###############################################################
#  Generated by:      Cadence Innovus 23.14-s088_1
#  OS:                Linux x86_64(Host ID user1-EliteMini)
#  Generated on:      Tue Oct 13 20:43:39 2026
#  Design:            top_soc
#  Command:           write_lef_abstract -noCutObs ./outputs/top_soc.lef
###############################################################

VERSION 5.8 ;

BUSBITCHARS "[]" ;
DIVIDERCHAR "/" ;

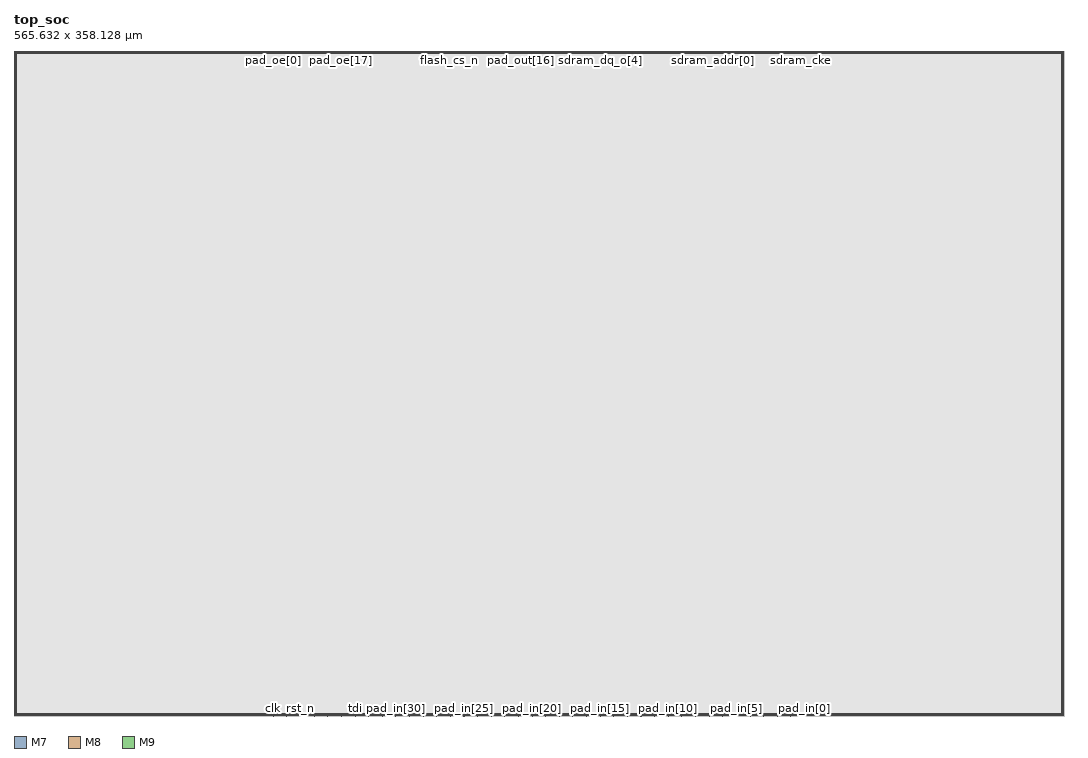
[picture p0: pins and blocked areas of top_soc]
MACRO top_soc
  CLASS BLOCK ;
  SIZE 565.632000 BY 358.128000 ;
  FOREIGN top_soc 0.000000 0.000000 ;
  ORIGIN 0 0 ;
  SYMMETRY X Y R90 ;
  PIN clk
    DIRECTION INPUT ;
    USE SIGNAL ;
    PORT
      LAYER M7 ;
        RECT 139.668000 0.000000 139.700000 0.072000 ;
    END
  END clk
  PIN rtc_clk
    DIRECTION INPUT ;
    USE SIGNAL ;
    PORT
      LAYER M7 ;
        RECT 146.964000 0.000000 146.996000 0.072000 ;
    END
  END rtc_clk
  PIN rst_n
    DIRECTION INPUT ;
    USE SIGNAL ;
    PORT
      LAYER M7 ;
        RECT 154.324000 0.000000 154.356000 0.072000 ;
    END
  END rst_n
  PIN tck
    DIRECTION INPUT ;
    USE SIGNAL ;
    PORT
      LAYER M7 ;
        RECT 161.684000 0.000000 161.716000 0.072000 ;
    END
  END tck
  PIN trst_n
    DIRECTION INPUT ;
    USE SIGNAL ;
    PORT
      LAYER M7 ;
        RECT 168.980000 0.000000 169.012000 0.072000 ;
    END
  END trst_n
  PIN tms
    DIRECTION INPUT ;
    USE SIGNAL ;
    PORT
      LAYER M7 ;
        RECT 176.340000 0.000000 176.372000 0.072000 ;
    END
  END tms
  PIN tdi
    DIRECTION INPUT ;
    USE SIGNAL ;
    PORT
      LAYER M7 ;
        RECT 183.700000 0.000000 183.732000 0.072000 ;
    END
  END tdi
  PIN tdo
    DIRECTION OUTPUT ;
    USE SIGNAL ;
    PORT
      LAYER M7 ;
        RECT 190.996000 0.000000 191.028000 0.072000 ;
    END
  END tdo
  PIN pad_in[31]
    DIRECTION INPUT ;
    USE SIGNAL ;
    PORT
      LAYER M7 ;
        RECT 198.356000 0.000000 198.388000 0.072000 ;
    END
  END pad_in[31]
  PIN pad_in[30]
    DIRECTION INPUT ;
    USE SIGNAL ;
    PORT
      LAYER M7 ;
        RECT 205.716000 0.000000 205.748000 0.072000 ;
    END
  END pad_in[30]
  PIN pad_in[29]
    DIRECTION INPUT ;
    USE SIGNAL ;
    PORT
      LAYER M7 ;
        RECT 213.012000 0.000000 213.044000 0.072000 ;
    END
  END pad_in[29]
  PIN pad_in[28]
    DIRECTION INPUT ;
    USE SIGNAL ;
    PORT
      LAYER M7 ;
        RECT 220.372000 0.000000 220.404000 0.072000 ;
    END
  END pad_in[28]
  PIN pad_in[27]
    DIRECTION INPUT ;
    USE SIGNAL ;
    PORT
      LAYER M7 ;
        RECT 227.732000 0.000000 227.764000 0.072000 ;
    END
  END pad_in[27]
  PIN pad_in[26]
    DIRECTION INPUT ;
    USE SIGNAL ;
    PORT
      LAYER M7 ;
        RECT 235.028000 0.000000 235.060000 0.072000 ;
    END
  END pad_in[26]
  PIN pad_in[25]
    DIRECTION INPUT ;
    USE SIGNAL ;
    PORT
      LAYER M7 ;
        RECT 242.388000 0.000000 242.420000 0.072000 ;
    END
  END pad_in[25]
  PIN pad_in[24]
    DIRECTION INPUT ;
    USE SIGNAL ;
    PORT
      LAYER M7 ;
        RECT 249.748000 0.000000 249.780000 0.072000 ;
    END
  END pad_in[24]
  PIN pad_in[23]
    DIRECTION INPUT ;
    USE SIGNAL ;
    PORT
      LAYER M7 ;
        RECT 257.044000 0.000000 257.076000 0.072000 ;
    END
  END pad_in[23]
  PIN pad_in[22]
    DIRECTION INPUT ;
    USE SIGNAL ;
    PORT
      LAYER M7 ;
        RECT 264.404000 0.000000 264.436000 0.072000 ;
    END
  END pad_in[22]
  PIN pad_in[21]
    DIRECTION INPUT ;
    USE SIGNAL ;
    PORT
      LAYER M7 ;
        RECT 271.764000 0.000000 271.796000 0.072000 ;
    END
  END pad_in[21]
  PIN pad_in[20]
    DIRECTION INPUT ;
    USE SIGNAL ;
    PORT
      LAYER M7 ;
        RECT 279.060000 0.000000 279.092000 0.072000 ;
    END
  END pad_in[20]
  PIN pad_in[19]
    DIRECTION INPUT ;
    USE SIGNAL ;
    PORT
      LAYER M7 ;
        RECT 286.420000 0.000000 286.452000 0.072000 ;
    END
  END pad_in[19]
  PIN pad_in[18]
    DIRECTION INPUT ;
    USE SIGNAL ;
    PORT
      LAYER M7 ;
        RECT 293.780000 0.000000 293.812000 0.072000 ;
    END
  END pad_in[18]
  PIN pad_in[17]
    DIRECTION INPUT ;
    USE SIGNAL ;
    PORT
      LAYER M7 ;
        RECT 301.076000 0.000000 301.108000 0.072000 ;
    END
  END pad_in[17]
  PIN pad_in[16]
    DIRECTION INPUT ;
    USE SIGNAL ;
    PORT
      LAYER M7 ;
        RECT 308.436000 0.000000 308.468000 0.072000 ;
    END
  END pad_in[16]
  PIN pad_in[15]
    DIRECTION INPUT ;
    USE SIGNAL ;
    PORT
      LAYER M7 ;
        RECT 315.732000 0.000000 315.764000 0.072000 ;
    END
  END pad_in[15]
  PIN pad_in[14]
    DIRECTION INPUT ;
    USE SIGNAL ;
    PORT
      LAYER M7 ;
        RECT 323.092000 0.000000 323.124000 0.072000 ;
    END
  END pad_in[14]
  PIN pad_in[13]
    DIRECTION INPUT ;
    USE SIGNAL ;
    PORT
      LAYER M7 ;
        RECT 330.452000 0.000000 330.484000 0.072000 ;
    END
  END pad_in[13]
  PIN pad_in[12]
    DIRECTION INPUT ;
    USE SIGNAL ;
    PORT
      LAYER M7 ;
        RECT 337.748000 0.000000 337.780000 0.072000 ;
    END
  END pad_in[12]
  PIN pad_in[11]
    DIRECTION INPUT ;
    USE SIGNAL ;
    PORT
      LAYER M7 ;
        RECT 345.108000 0.000000 345.140000 0.072000 ;
    END
  END pad_in[11]
  PIN pad_in[10]
    DIRECTION INPUT ;
    USE SIGNAL ;
    PORT
      LAYER M7 ;
        RECT 352.468000 0.000000 352.500000 0.072000 ;
    END
  END pad_in[10]
  PIN pad_in[9]
    DIRECTION INPUT ;
    USE SIGNAL ;
    PORT
      LAYER M7 ;
        RECT 359.764000 0.000000 359.796000 0.072000 ;
    END
  END pad_in[9]
  PIN pad_in[8]
    DIRECTION INPUT ;
    USE SIGNAL ;
    PORT
      LAYER M7 ;
        RECT 367.124000 0.000000 367.156000 0.072000 ;
    END
  END pad_in[8]
  PIN pad_in[7]
    DIRECTION INPUT ;
    USE SIGNAL ;
    PORT
      LAYER M7 ;
        RECT 374.484000 0.000000 374.516000 0.072000 ;
    END
  END pad_in[7]
  PIN pad_in[6]
    DIRECTION INPUT ;
    USE SIGNAL ;
    PORT
      LAYER M7 ;
        RECT 381.780000 0.000000 381.812000 0.072000 ;
    END
  END pad_in[6]
  PIN pad_in[5]
    DIRECTION INPUT ;
    USE SIGNAL ;
    PORT
      LAYER M7 ;
        RECT 389.140000 0.000000 389.172000 0.072000 ;
    END
  END pad_in[5]
  PIN pad_in[4]
    DIRECTION INPUT ;
    USE SIGNAL ;
    PORT
      LAYER M7 ;
        RECT 396.500000 0.000000 396.532000 0.072000 ;
    END
  END pad_in[4]
  PIN pad_in[3]
    DIRECTION INPUT ;
    USE SIGNAL ;
    PORT
      LAYER M7 ;
        RECT 403.796000 0.000000 403.828000 0.072000 ;
    END
  END pad_in[3]
  PIN pad_in[2]
    DIRECTION INPUT ;
    USE SIGNAL ;
    PORT
      LAYER M7 ;
        RECT 411.156000 0.000000 411.188000 0.072000 ;
    END
  END pad_in[2]
  PIN pad_in[1]
    DIRECTION INPUT ;
    USE SIGNAL ;
    PORT
      LAYER M7 ;
        RECT 418.516000 0.000000 418.548000 0.072000 ;
    END
  END pad_in[1]
  PIN pad_in[0]
    DIRECTION INPUT ;
    USE SIGNAL ;
    PORT
      LAYER M7 ;
        RECT 425.812000 0.000000 425.844000 0.072000 ;
    END
  END pad_in[0]
  PIN pad_out[31]
    DIRECTION OUTPUT ;
    USE SIGNAL ;
    PORT
      LAYER M7 ;
        RECT 305.428000 358.056000 305.460000 358.128000 ;
    END
  END pad_out[31]
  PIN pad_out[30]
    DIRECTION OUTPUT ;
    USE SIGNAL ;
    PORT
      LAYER M7 ;
        RECT 303.252000 358.056000 303.284000 358.128000 ;
    END
  END pad_out[30]
  PIN pad_out[29]
    DIRECTION OUTPUT ;
    USE SIGNAL ;
    PORT
      LAYER M7 ;
        RECT 301.076000 358.056000 301.108000 358.128000 ;
    END
  END pad_out[29]
  PIN pad_out[28]
    DIRECTION OUTPUT ;
    USE SIGNAL ;
    PORT
      LAYER M7 ;
        RECT 298.964000 358.056000 298.996000 358.128000 ;
    END
  END pad_out[28]
  PIN pad_out[27]
    DIRECTION OUTPUT ;
    USE SIGNAL ;
    PORT
      LAYER M7 ;
        RECT 296.788000 358.056000 296.820000 358.128000 ;
    END
  END pad_out[27]
  PIN pad_out[26]
    DIRECTION OUTPUT ;
    USE SIGNAL ;
    PORT
      LAYER M7 ;
        RECT 294.612000 358.056000 294.644000 358.128000 ;
    END
  END pad_out[26]
  PIN pad_out[25]
    DIRECTION OUTPUT ;
    USE SIGNAL ;
    PORT
      LAYER M7 ;
        RECT 292.500000 358.056000 292.532000 358.128000 ;
    END
  END pad_out[25]
  PIN pad_out[24]
    DIRECTION OUTPUT ;
    USE SIGNAL ;
    PORT
      LAYER M7 ;
        RECT 290.324000 358.056000 290.356000 358.128000 ;
    END
  END pad_out[24]
  PIN pad_out[23]
    DIRECTION OUTPUT ;
    USE SIGNAL ;
    PORT
      LAYER M7 ;
        RECT 288.212000 358.056000 288.244000 358.128000 ;
    END
  END pad_out[23]
  PIN pad_out[22]
    DIRECTION OUTPUT ;
    USE SIGNAL ;
    PORT
      LAYER M7 ;
        RECT 286.036000 358.056000 286.068000 358.128000 ;
    END
  END pad_out[22]
  PIN pad_out[21]
    DIRECTION OUTPUT ;
    USE SIGNAL ;
    PORT
      LAYER M7 ;
        RECT 283.860000 358.056000 283.892000 358.128000 ;
    END
  END pad_out[21]
  PIN pad_out[20]
    DIRECTION OUTPUT ;
    USE SIGNAL ;
    PORT
      LAYER M7 ;
        RECT 281.748000 358.056000 281.780000 358.128000 ;
    END
  END pad_out[20]
  PIN pad_out[19]
    DIRECTION OUTPUT ;
    USE SIGNAL ;
    PORT
      LAYER M7 ;
        RECT 279.572000 358.056000 279.604000 358.128000 ;
    END
  END pad_out[19]
  PIN pad_out[18]
    DIRECTION OUTPUT ;
    USE SIGNAL ;
    PORT
      LAYER M7 ;
        RECT 277.396000 358.056000 277.428000 358.128000 ;
    END
  END pad_out[18]
  PIN pad_out[17]
    DIRECTION OUTPUT ;
    USE SIGNAL ;
    PORT
      LAYER M7 ;
        RECT 275.284000 358.056000 275.316000 358.128000 ;
    END
  END pad_out[17]
  PIN pad_out[16]
    DIRECTION OUTPUT ;
    USE SIGNAL ;
    PORT
      LAYER M7 ;
        RECT 273.108000 358.056000 273.140000 358.128000 ;
    END
  END pad_out[16]
  PIN pad_out[15]
    DIRECTION OUTPUT ;
    USE SIGNAL ;
    PORT
      LAYER M7 ;
        RECT 270.996000 358.056000 271.028000 358.128000 ;
    END
  END pad_out[15]
  PIN pad_out[14]
    DIRECTION OUTPUT ;
    USE SIGNAL ;
    PORT
      LAYER M7 ;
        RECT 268.820000 358.056000 268.852000 358.128000 ;
    END
  END pad_out[14]
  PIN pad_out[13]
    DIRECTION OUTPUT ;
    USE SIGNAL ;
    PORT
      LAYER M7 ;
        RECT 266.644000 358.056000 266.676000 358.128000 ;
    END
  END pad_out[13]
  PIN pad_out[12]
    DIRECTION OUTPUT ;
    USE SIGNAL ;
    PORT
      LAYER M7 ;
        RECT 264.532000 358.056000 264.564000 358.128000 ;
    END
  END pad_out[12]
  PIN pad_out[11]
    DIRECTION OUTPUT ;
    USE SIGNAL ;
    PORT
      LAYER M7 ;
        RECT 262.356000 358.056000 262.388000 358.128000 ;
    END
  END pad_out[11]
  PIN pad_out[10]
    DIRECTION OUTPUT ;
    USE SIGNAL ;
    PORT
      LAYER M7 ;
        RECT 260.180000 358.056000 260.212000 358.128000 ;
    END
  END pad_out[10]
  PIN pad_out[9]
    DIRECTION OUTPUT ;
    USE SIGNAL ;
    PORT
      LAYER M7 ;
        RECT 258.068000 358.056000 258.100000 358.128000 ;
    END
  END pad_out[9]
  PIN pad_out[8]
    DIRECTION OUTPUT ;
    USE SIGNAL ;
    PORT
      LAYER M7 ;
        RECT 255.892000 358.056000 255.924000 358.128000 ;
    END
  END pad_out[8]
  PIN pad_out[7]
    DIRECTION OUTPUT ;
    USE SIGNAL ;
    PORT
      LAYER M7 ;
        RECT 253.780000 358.056000 253.812000 358.128000 ;
    END
  END pad_out[7]
  PIN pad_out[6]
    DIRECTION OUTPUT ;
    USE SIGNAL ;
    PORT
      LAYER M7 ;
        RECT 251.604000 358.056000 251.636000 358.128000 ;
    END
  END pad_out[6]
  PIN pad_out[5]
    DIRECTION OUTPUT ;
    USE SIGNAL ;
    PORT
      LAYER M7 ;
        RECT 249.428000 358.056000 249.460000 358.128000 ;
    END
  END pad_out[5]
  PIN pad_out[4]
    DIRECTION OUTPUT ;
    USE SIGNAL ;
    PORT
      LAYER M7 ;
        RECT 247.316000 358.056000 247.348000 358.128000 ;
    END
  END pad_out[4]
  PIN pad_out[3]
    DIRECTION OUTPUT ;
    USE SIGNAL ;
    PORT
      LAYER M7 ;
        RECT 245.140000 358.056000 245.172000 358.128000 ;
    END
  END pad_out[3]
  PIN pad_out[2]
    DIRECTION OUTPUT ;
    USE SIGNAL ;
    PORT
      LAYER M7 ;
        RECT 242.964000 358.056000 242.996000 358.128000 ;
    END
  END pad_out[2]
  PIN pad_out[1]
    DIRECTION OUTPUT ;
    USE SIGNAL ;
    PORT
      LAYER M7 ;
        RECT 240.852000 358.056000 240.884000 358.128000 ;
    END
  END pad_out[1]
  PIN pad_out[0]
    DIRECTION OUTPUT ;
    USE SIGNAL ;
    PORT
      LAYER M7 ;
        RECT 238.676000 358.056000 238.708000 358.128000 ;
    END
  END pad_out[0]
  PIN pad_oe[31]
    DIRECTION OUTPUT ;
    USE SIGNAL ;
    PORT
      LAYER M7 ;
        RECT 206.420000 358.056000 206.452000 358.128000 ;
    END
  END pad_oe[31]
  PIN pad_oe[30]
    DIRECTION OUTPUT ;
    USE SIGNAL ;
    PORT
      LAYER M7 ;
        RECT 204.244000 358.056000 204.276000 358.128000 ;
    END
  END pad_oe[30]
  PIN pad_oe[29]
    DIRECTION OUTPUT ;
    USE SIGNAL ;
    PORT
      LAYER M7 ;
        RECT 202.132000 358.056000 202.164000 358.128000 ;
    END
  END pad_oe[29]
  PIN pad_oe[28]
    DIRECTION OUTPUT ;
    USE SIGNAL ;
    PORT
      LAYER M7 ;
        RECT 199.956000 358.056000 199.988000 358.128000 ;
    END
  END pad_oe[28]
  PIN pad_oe[27]
    DIRECTION OUTPUT ;
    USE SIGNAL ;
    PORT
      LAYER M7 ;
        RECT 197.780000 358.056000 197.812000 358.128000 ;
    END
  END pad_oe[27]
  PIN pad_oe[26]
    DIRECTION OUTPUT ;
    USE SIGNAL ;
    PORT
      LAYER M7 ;
        RECT 195.668000 358.056000 195.700000 358.128000 ;
    END
  END pad_oe[26]
  PIN pad_oe[25]
    DIRECTION OUTPUT ;
    USE SIGNAL ;
    PORT
      LAYER M7 ;
        RECT 193.492000 358.056000 193.524000 358.128000 ;
    END
  END pad_oe[25]
  PIN pad_oe[24]
    DIRECTION OUTPUT ;
    USE SIGNAL ;
    PORT
      LAYER M7 ;
        RECT 191.316000 358.056000 191.348000 358.128000 ;
    END
  END pad_oe[24]
  PIN pad_oe[23]
    DIRECTION OUTPUT ;
    USE SIGNAL ;
    PORT
      LAYER M7 ;
        RECT 189.204000 358.056000 189.236000 358.128000 ;
    END
  END pad_oe[23]
  PIN pad_oe[22]
    DIRECTION OUTPUT ;
    USE SIGNAL ;
    PORT
      LAYER M7 ;
        RECT 187.028000 358.056000 187.060000 358.128000 ;
    END
  END pad_oe[22]
  PIN pad_oe[21]
    DIRECTION OUTPUT ;
    USE SIGNAL ;
    PORT
      LAYER M7 ;
        RECT 184.916000 358.056000 184.948000 358.128000 ;
    END
  END pad_oe[21]
  PIN pad_oe[20]
    DIRECTION OUTPUT ;
    USE SIGNAL ;
    PORT
      LAYER M7 ;
        RECT 182.740000 358.056000 182.772000 358.128000 ;
    END
  END pad_oe[20]
  PIN pad_oe[19]
    DIRECTION OUTPUT ;
    USE SIGNAL ;
    PORT
      LAYER M7 ;
        RECT 180.564000 358.056000 180.596000 358.128000 ;
    END
  END pad_oe[19]
  PIN pad_oe[18]
    DIRECTION OUTPUT ;
    USE SIGNAL ;
    PORT
      LAYER M7 ;
        RECT 178.452000 358.056000 178.484000 358.128000 ;
    END
  END pad_oe[18]
  PIN pad_oe[17]
    DIRECTION OUTPUT ;
    USE SIGNAL ;
    PORT
      LAYER M7 ;
        RECT 176.276000 358.056000 176.308000 358.128000 ;
    END
  END pad_oe[17]
  PIN pad_oe[16]
    DIRECTION OUTPUT ;
    USE SIGNAL ;
    PORT
      LAYER M7 ;
        RECT 174.100000 358.056000 174.132000 358.128000 ;
    END
  END pad_oe[16]
  PIN pad_oe[15]
    DIRECTION OUTPUT ;
    USE SIGNAL ;
    PORT
      LAYER M7 ;
        RECT 171.988000 358.056000 172.020000 358.128000 ;
    END
  END pad_oe[15]
  PIN pad_oe[14]
    DIRECTION OUTPUT ;
    USE SIGNAL ;
    PORT
      LAYER M7 ;
        RECT 169.812000 358.056000 169.844000 358.128000 ;
    END
  END pad_oe[14]
  PIN pad_oe[13]
    DIRECTION OUTPUT ;
    USE SIGNAL ;
    PORT
      LAYER M7 ;
        RECT 167.700000 358.056000 167.732000 358.128000 ;
    END
  END pad_oe[13]
  PIN pad_oe[12]
    DIRECTION OUTPUT ;
    USE SIGNAL ;
    PORT
      LAYER M7 ;
        RECT 165.524000 358.056000 165.556000 358.128000 ;
    END
  END pad_oe[12]
  PIN pad_oe[11]
    DIRECTION OUTPUT ;
    USE SIGNAL ;
    PORT
      LAYER M7 ;
        RECT 163.348000 358.056000 163.380000 358.128000 ;
    END
  END pad_oe[11]
  PIN pad_oe[10]
    DIRECTION OUTPUT ;
    USE SIGNAL ;
    PORT
      LAYER M7 ;
        RECT 161.236000 358.056000 161.268000 358.128000 ;
    END
  END pad_oe[10]
  PIN pad_oe[9]
    DIRECTION OUTPUT ;
    USE SIGNAL ;
    PORT
      LAYER M7 ;
        RECT 159.060000 358.056000 159.092000 358.128000 ;
    END
  END pad_oe[9]
  PIN pad_oe[8]
    DIRECTION OUTPUT ;
    USE SIGNAL ;
    PORT
      LAYER M7 ;
        RECT 156.884000 358.056000 156.916000 358.128000 ;
    END
  END pad_oe[8]
  PIN pad_oe[7]
    DIRECTION OUTPUT ;
    USE SIGNAL ;
    PORT
      LAYER M7 ;
        RECT 154.772000 358.056000 154.804000 358.128000 ;
    END
  END pad_oe[7]
  PIN pad_oe[6]
    DIRECTION OUTPUT ;
    USE SIGNAL ;
    PORT
      LAYER M7 ;
        RECT 152.596000 358.056000 152.628000 358.128000 ;
    END
  END pad_oe[6]
  PIN pad_oe[5]
    DIRECTION OUTPUT ;
    USE SIGNAL ;
    PORT
      LAYER M7 ;
        RECT 150.484000 358.056000 150.516000 358.128000 ;
    END
  END pad_oe[5]
  PIN pad_oe[4]
    DIRECTION OUTPUT ;
    USE SIGNAL ;
    PORT
      LAYER M7 ;
        RECT 148.308000 358.056000 148.340000 358.128000 ;
    END
  END pad_oe[4]
  PIN pad_oe[3]
    DIRECTION OUTPUT ;
    USE SIGNAL ;
    PORT
      LAYER M7 ;
        RECT 146.132000 358.056000 146.164000 358.128000 ;
    END
  END pad_oe[3]
  PIN pad_oe[2]
    DIRECTION OUTPUT ;
    USE SIGNAL ;
    PORT
      LAYER M7 ;
        RECT 144.020000 358.056000 144.052000 358.128000 ;
    END
  END pad_oe[2]
  PIN pad_oe[1]
    DIRECTION OUTPUT ;
    USE SIGNAL ;
    PORT
      LAYER M7 ;
        RECT 141.844000 358.056000 141.876000 358.128000 ;
    END
  END pad_oe[1]
  PIN pad_oe[0]
    DIRECTION OUTPUT ;
    USE SIGNAL ;
    PORT
      LAYER M7 ;
        RECT 139.668000 358.056000 139.700000 358.128000 ;
    END
  END pad_oe[0]
  PIN flash_sck
    DIRECTION OUTPUT ;
    USE SIGNAL ;
    PORT
      LAYER M7 ;
        RECT 236.564000 358.056000 236.596000 358.128000 ;
    END
  END flash_sck
  PIN flash_cs_n
    DIRECTION OUTPUT ;
    USE SIGNAL ;
    PORT
      LAYER M7 ;
        RECT 234.388000 358.056000 234.420000 358.128000 ;
    END
  END flash_cs_n
  PIN flash_io_i[3]
    DIRECTION INPUT ;
    USE SIGNAL ;
    PORT
      LAYER M7 ;
        RECT 232.212000 358.056000 232.244000 358.128000 ;
    END
  END flash_io_i[3]
  PIN flash_io_i[2]
    DIRECTION INPUT ;
    USE SIGNAL ;
    PORT
      LAYER M7 ;
        RECT 230.100000 358.056000 230.132000 358.128000 ;
    END
  END flash_io_i[2]
  PIN flash_io_i[1]
    DIRECTION INPUT ;
    USE SIGNAL ;
    PORT
      LAYER M7 ;
        RECT 227.924000 358.056000 227.956000 358.128000 ;
    END
  END flash_io_i[1]
  PIN flash_io_i[0]
    DIRECTION INPUT ;
    USE SIGNAL ;
    PORT
      LAYER M7 ;
        RECT 225.748000 358.056000 225.780000 358.128000 ;
    END
  END flash_io_i[0]
  PIN flash_io_o[3]
    DIRECTION OUTPUT ;
    USE SIGNAL ;
    PORT
      LAYER M7 ;
        RECT 223.636000 358.056000 223.668000 358.128000 ;
    END
  END flash_io_o[3]
  PIN flash_io_o[2]
    DIRECTION OUTPUT ;
    USE SIGNAL ;
    PORT
      LAYER M7 ;
        RECT 221.460000 358.056000 221.492000 358.128000 ;
    END
  END flash_io_o[2]
  PIN flash_io_o[1]
    DIRECTION OUTPUT ;
    USE SIGNAL ;
    PORT
      LAYER M7 ;
        RECT 219.348000 358.056000 219.380000 358.128000 ;
    END
  END flash_io_o[1]
  PIN flash_io_o[0]
    DIRECTION OUTPUT ;
    USE SIGNAL ;
    PORT
      LAYER M7 ;
        RECT 217.172000 358.056000 217.204000 358.128000 ;
    END
  END flash_io_o[0]
  PIN flash_io_oe[3]
    DIRECTION OUTPUT ;
    USE SIGNAL ;
    PORT
      LAYER M7 ;
        RECT 214.996000 358.056000 215.028000 358.128000 ;
    END
  END flash_io_oe[3]
  PIN flash_io_oe[2]
    DIRECTION OUTPUT ;
    USE SIGNAL ;
    PORT
      LAYER M7 ;
        RECT 212.884000 358.056000 212.916000 358.128000 ;
    END
  END flash_io_oe[2]
  PIN flash_io_oe[1]
    DIRECTION OUTPUT ;
    USE SIGNAL ;
    PORT
      LAYER M7 ;
        RECT 210.708000 358.056000 210.740000 358.128000 ;
    END
  END flash_io_oe[1]
  PIN flash_io_oe[0]
    DIRECTION OUTPUT ;
    USE SIGNAL ;
    PORT
      LAYER M7 ;
        RECT 208.532000 358.056000 208.564000 358.128000 ;
    END
  END flash_io_oe[0]
  PIN sdram_clk
    DIRECTION OUTPUT ;
    USE SIGNAL ;
    PORT
      LAYER M7 ;
        RECT 425.876000 358.056000 425.908000 358.128000 ;
    END
  END sdram_clk
  PIN sdram_cke
    DIRECTION OUTPUT ;
    USE SIGNAL ;
    PORT
      LAYER M7 ;
        RECT 423.764000 358.056000 423.796000 358.128000 ;
    END
  END sdram_cke
  PIN sdram_cs_n
    DIRECTION OUTPUT ;
    USE SIGNAL ;
    PORT
      LAYER M7 ;
        RECT 421.588000 358.056000 421.620000 358.128000 ;
    END
  END sdram_cs_n
  PIN sdram_ras_n
    DIRECTION OUTPUT ;
    USE SIGNAL ;
    PORT
      LAYER M7 ;
        RECT 419.476000 358.056000 419.508000 358.128000 ;
    END
  END sdram_ras_n
  PIN sdram_cas_n
    DIRECTION OUTPUT ;
    USE SIGNAL ;
    PORT
      LAYER M7 ;
        RECT 417.300000 358.056000 417.332000 358.128000 ;
    END
  END sdram_cas_n
  PIN sdram_we_n
    DIRECTION OUTPUT ;
    USE SIGNAL ;
    PORT
      LAYER M7 ;
        RECT 415.124000 358.056000 415.156000 358.128000 ;
    END
  END sdram_we_n
  PIN sdram_ba[1]
    DIRECTION OUTPUT ;
    USE SIGNAL ;
    PORT
      LAYER M7 ;
        RECT 410.836000 358.056000 410.868000 358.128000 ;
    END
  END sdram_ba[1]
  PIN sdram_ba[0]
    DIRECTION OUTPUT ;
    USE SIGNAL ;
    PORT
      LAYER M7 ;
        RECT 408.724000 358.056000 408.756000 358.128000 ;
    END
  END sdram_ba[0]
  PIN sdram_addr[12]
    DIRECTION OUTPUT ;
    USE SIGNAL ;
    PORT
      LAYER M7 ;
        RECT 402.260000 358.056000 402.292000 358.128000 ;
    END
  END sdram_addr[12]
  PIN sdram_addr[11]
    DIRECTION OUTPUT ;
    USE SIGNAL ;
    PORT
      LAYER M7 ;
        RECT 400.084000 358.056000 400.116000 358.128000 ;
    END
  END sdram_addr[11]
  PIN sdram_addr[10]
    DIRECTION OUTPUT ;
    USE SIGNAL ;
    PORT
      LAYER M7 ;
        RECT 397.908000 358.056000 397.940000 358.128000 ;
    END
  END sdram_addr[10]
  PIN sdram_addr[9]
    DIRECTION OUTPUT ;
    USE SIGNAL ;
    PORT
      LAYER M7 ;
        RECT 395.796000 358.056000 395.828000 358.128000 ;
    END
  END sdram_addr[9]
  PIN sdram_addr[8]
    DIRECTION OUTPUT ;
    USE SIGNAL ;
    PORT
      LAYER M7 ;
        RECT 393.620000 358.056000 393.652000 358.128000 ;
    END
  END sdram_addr[8]
  PIN sdram_addr[7]
    DIRECTION OUTPUT ;
    USE SIGNAL ;
    PORT
      LAYER M7 ;
        RECT 391.508000 358.056000 391.540000 358.128000 ;
    END
  END sdram_addr[7]
  PIN sdram_addr[6]
    DIRECTION OUTPUT ;
    USE SIGNAL ;
    PORT
      LAYER M7 ;
        RECT 389.332000 358.056000 389.364000 358.128000 ;
    END
  END sdram_addr[6]
  PIN sdram_addr[5]
    DIRECTION OUTPUT ;
    USE SIGNAL ;
    PORT
      LAYER M7 ;
        RECT 387.156000 358.056000 387.188000 358.128000 ;
    END
  END sdram_addr[5]
  PIN sdram_addr[4]
    DIRECTION OUTPUT ;
    USE SIGNAL ;
    PORT
      LAYER M7 ;
        RECT 385.044000 358.056000 385.076000 358.128000 ;
    END
  END sdram_addr[4]
  PIN sdram_addr[3]
    DIRECTION OUTPUT ;
    USE SIGNAL ;
    PORT
      LAYER M7 ;
        RECT 382.868000 358.056000 382.900000 358.128000 ;
    END
  END sdram_addr[3]
  PIN sdram_addr[2]
    DIRECTION OUTPUT ;
    USE SIGNAL ;
    PORT
      LAYER M7 ;
        RECT 380.692000 358.056000 380.724000 358.128000 ;
    END
  END sdram_addr[2]
  PIN sdram_addr[1]
    DIRECTION OUTPUT ;
    USE SIGNAL ;
    PORT
      LAYER M7 ;
        RECT 378.580000 358.056000 378.612000 358.128000 ;
    END
  END sdram_addr[1]
  PIN sdram_addr[0]
    DIRECTION OUTPUT ;
    USE SIGNAL ;
    PORT
      LAYER M7 ;
        RECT 376.404000 358.056000 376.436000 358.128000 ;
    END
  END sdram_addr[0]
  PIN sdram_dq_i[15]
    DIRECTION INPUT ;
    USE SIGNAL ;
    PORT
      LAYER M7 ;
        RECT 374.292000 358.056000 374.324000 358.128000 ;
    END
  END sdram_dq_i[15]
  PIN sdram_dq_i[14]
    DIRECTION INPUT ;
    USE SIGNAL ;
    PORT
      LAYER M7 ;
        RECT 372.116000 358.056000 372.148000 358.128000 ;
    END
  END sdram_dq_i[14]
  PIN sdram_dq_i[13]
    DIRECTION INPUT ;
    USE SIGNAL ;
    PORT
      LAYER M7 ;
        RECT 369.940000 358.056000 369.972000 358.128000 ;
    END
  END sdram_dq_i[13]
  PIN sdram_dq_i[12]
    DIRECTION INPUT ;
    USE SIGNAL ;
    PORT
      LAYER M7 ;
        RECT 367.828000 358.056000 367.860000 358.128000 ;
    END
  END sdram_dq_i[12]
  PIN sdram_dq_i[11]
    DIRECTION INPUT ;
    USE SIGNAL ;
    PORT
      LAYER M7 ;
        RECT 365.652000 358.056000 365.684000 358.128000 ;
    END
  END sdram_dq_i[11]
  PIN sdram_dq_i[10]
    DIRECTION INPUT ;
    USE SIGNAL ;
    PORT
      LAYER M7 ;
        RECT 363.476000 358.056000 363.508000 358.128000 ;
    END
  END sdram_dq_i[10]
  PIN sdram_dq_i[9]
    DIRECTION INPUT ;
    USE SIGNAL ;
    PORT
      LAYER M7 ;
        RECT 361.364000 358.056000 361.396000 358.128000 ;
    END
  END sdram_dq_i[9]
  PIN sdram_dq_i[8]
    DIRECTION INPUT ;
    USE SIGNAL ;
    PORT
      LAYER M7 ;
        RECT 359.188000 358.056000 359.220000 358.128000 ;
    END
  END sdram_dq_i[8]
  PIN sdram_dq_i[7]
    DIRECTION INPUT ;
    USE SIGNAL ;
    PORT
      LAYER M7 ;
        RECT 357.076000 358.056000 357.108000 358.128000 ;
    END
  END sdram_dq_i[7]
  PIN sdram_dq_i[6]
    DIRECTION INPUT ;
    USE SIGNAL ;
    PORT
      LAYER M7 ;
        RECT 354.900000 358.056000 354.932000 358.128000 ;
    END
  END sdram_dq_i[6]
  PIN sdram_dq_i[5]
    DIRECTION INPUT ;
    USE SIGNAL ;
    PORT
      LAYER M7 ;
        RECT 352.724000 358.056000 352.756000 358.128000 ;
    END
  END sdram_dq_i[5]
  PIN sdram_dq_i[4]
    DIRECTION INPUT ;
    USE SIGNAL ;
    PORT
      LAYER M7 ;
        RECT 350.612000 358.056000 350.644000 358.128000 ;
    END
  END sdram_dq_i[4]
  PIN sdram_dq_i[3]
    DIRECTION INPUT ;
    USE SIGNAL ;
    PORT
      LAYER M7 ;
        RECT 348.436000 358.056000 348.468000 358.128000 ;
    END
  END sdram_dq_i[3]
  PIN sdram_dq_i[2]
    DIRECTION INPUT ;
    USE SIGNAL ;
    PORT
      LAYER M7 ;
        RECT 346.260000 358.056000 346.292000 358.128000 ;
    END
  END sdram_dq_i[2]
  PIN sdram_dq_i[1]
    DIRECTION INPUT ;
    USE SIGNAL ;
    PORT
      LAYER M7 ;
        RECT 344.148000 358.056000 344.180000 358.128000 ;
    END
  END sdram_dq_i[1]
  PIN sdram_dq_i[0]
    DIRECTION INPUT ;
    USE SIGNAL ;
    PORT
      LAYER M7 ;
        RECT 341.972000 358.056000 342.004000 358.128000 ;
    END
  END sdram_dq_i[0]
  PIN sdram_dq_o[15]
    DIRECTION OUTPUT ;
    USE SIGNAL ;
    PORT
      LAYER M7 ;
        RECT 339.860000 358.056000 339.892000 358.128000 ;
    END
  END sdram_dq_o[15]
  PIN sdram_dq_o[14]
    DIRECTION OUTPUT ;
    USE SIGNAL ;
    PORT
      LAYER M7 ;
        RECT 337.684000 358.056000 337.716000 358.128000 ;
    END
  END sdram_dq_o[14]
  PIN sdram_dq_o[13]
    DIRECTION OUTPUT ;
    USE SIGNAL ;
    PORT
      LAYER M7 ;
        RECT 335.508000 358.056000 335.540000 358.128000 ;
    END
  END sdram_dq_o[13]
  PIN sdram_dq_o[12]
    DIRECTION OUTPUT ;
    USE SIGNAL ;
    PORT
      LAYER M7 ;
        RECT 333.396000 358.056000 333.428000 358.128000 ;
    END
  END sdram_dq_o[12]
  PIN sdram_dq_o[11]
    DIRECTION OUTPUT ;
    USE SIGNAL ;
    PORT
      LAYER M7 ;
        RECT 331.220000 358.056000 331.252000 358.128000 ;
    END
  END sdram_dq_o[11]
  PIN sdram_dq_o[10]
    DIRECTION OUTPUT ;
    USE SIGNAL ;
    PORT
      LAYER M7 ;
        RECT 329.044000 358.056000 329.076000 358.128000 ;
    END
  END sdram_dq_o[10]
  PIN sdram_dq_o[9]
    DIRECTION OUTPUT ;
    USE SIGNAL ;
    PORT
      LAYER M7 ;
        RECT 326.932000 358.056000 326.964000 358.128000 ;
    END
  END sdram_dq_o[9]
  PIN sdram_dq_o[8]
    DIRECTION OUTPUT ;
    USE SIGNAL ;
    PORT
      LAYER M7 ;
        RECT 324.756000 358.056000 324.788000 358.128000 ;
    END
  END sdram_dq_o[8]
  PIN sdram_dq_o[7]
    DIRECTION OUTPUT ;
    USE SIGNAL ;
    PORT
      LAYER M7 ;
        RECT 322.644000 358.056000 322.676000 358.128000 ;
    END
  END sdram_dq_o[7]
  PIN sdram_dq_o[6]
    DIRECTION OUTPUT ;
    USE SIGNAL ;
    PORT
      LAYER M7 ;
        RECT 320.468000 358.056000 320.500000 358.128000 ;
    END
  END sdram_dq_o[6]
  PIN sdram_dq_o[5]
    DIRECTION OUTPUT ;
    USE SIGNAL ;
    PORT
      LAYER M7 ;
        RECT 318.292000 358.056000 318.324000 358.128000 ;
    END
  END sdram_dq_o[5]
  PIN sdram_dq_o[4]
    DIRECTION OUTPUT ;
    USE SIGNAL ;
    PORT
      LAYER M7 ;
        RECT 316.180000 358.056000 316.212000 358.128000 ;
    END
  END sdram_dq_o[4]
  PIN sdram_dq_o[3]
    DIRECTION OUTPUT ;
    USE SIGNAL ;
    PORT
      LAYER M7 ;
        RECT 314.004000 358.056000 314.036000 358.128000 ;
    END
  END sdram_dq_o[3]
  PIN sdram_dq_o[2]
    DIRECTION OUTPUT ;
    USE SIGNAL ;
    PORT
      LAYER M7 ;
        RECT 311.828000 358.056000 311.860000 358.128000 ;
    END
  END sdram_dq_o[2]
  PIN sdram_dq_o[1]
    DIRECTION OUTPUT ;
    USE SIGNAL ;
    PORT
      LAYER M7 ;
        RECT 309.716000 358.056000 309.748000 358.128000 ;
    END
  END sdram_dq_o[1]
  PIN sdram_dq_o[0]
    DIRECTION OUTPUT ;
    USE SIGNAL ;
    PORT
      LAYER M7 ;
        RECT 307.540000 358.056000 307.572000 358.128000 ;
    END
  END sdram_dq_o[0]
  PIN sdram_dq_oe
    DIRECTION OUTPUT ;
    USE SIGNAL ;
    PORT
      LAYER M7 ;
        RECT 413.012000 358.056000 413.044000 358.128000 ;
    END
  END sdram_dq_oe
  PIN sdram_dqm[1]
    DIRECTION OUTPUT ;
    USE SIGNAL ;
    PORT
      LAYER M7 ;
        RECT 406.548000 358.056000 406.580000 358.128000 ;
    END
  END sdram_dqm[1]
  PIN sdram_dqm[0]
    DIRECTION OUTPUT ;
    USE SIGNAL ;
    PORT
      LAYER M7 ;
        RECT 404.372000 358.056000 404.404000 358.128000 ;
    END
  END sdram_dqm[0]
  PIN VDD
    DIRECTION INOUT ;
    USE POWER ;
    PORT
      LAYER M8 ;
        RECT 0.862000 0.836000 564.730000 1.316000 ;
    END
    PORT
      LAYER M9 ;
        RECT 564.276000 0.842000 564.756000 357.310000 ;
    END
    PORT
      LAYER M9 ;
        RECT 0.836000 0.842000 1.316000 357.310000 ;
    END
    PORT
      LAYER M8 ;
        RECT 0.862000 356.836000 564.730000 357.316000 ;
    END
  END VDD
  PIN VSS
    DIRECTION INOUT ;
    USE GROUND ;
    PORT
      LAYER M8 ;
        RECT 0.222000 0.196000 565.370000 0.676000 ;
    END
    PORT
      LAYER M9 ;
        RECT 564.916000 0.202000 565.396000 357.950000 ;
    END
    PORT
      LAYER M9 ;
        RECT 0.196000 0.202000 0.676000 357.950000 ;
    END
    PORT
      LAYER M8 ;
        RECT 0.222000 357.476000 565.370000 357.956000 ;
    END
  END VSS
  OBS
    LAYER M1 ;
      RECT 0.000000 0.000000 565.632000 358.128000 ;
    LAYER M2 ;
      RECT 0.000000 0.000000 565.632000 358.128000 ;
    LAYER M3 ;
      RECT 0.000000 0.000000 565.632000 358.128000 ;
    LAYER M4 ;
      RECT 0.000000 0.000000 565.632000 358.128000 ;
    LAYER M5 ;
      RECT 0.000000 0.000000 565.632000 358.128000 ;
    LAYER M6 ;
      RECT 0.000000 0.000000 565.632000 358.128000 ;
    LAYER M7 ;
      RECT 0.000000 0.000000 565.632000 358.128000 ;
    LAYER M8 ;
      RECT 0.000000 0.000000 565.632000 358.128000 ;
    LAYER M9 ;
      RECT 0.000000 0.000000 565.632000 358.128000 ;
    LAYER Pad ;
      RECT 0.000000 0.000000 565.632000 358.128000 ;
  END
  DENSITY
      LAYER M1 ;
      RECT 500.000000 300.000000 565.632000 358.128000 37.92 ;
      RECT 400.000000 300.000000 500.000000 358.128000 43.57 ;
      RECT 300.000000 300.000000 400.000000 358.128000 37.53 ;
      RECT 200.000000 300.000000 300.000000 358.128000 47.39 ;
      RECT 100.000000 300.000000 200.000000 358.128000 41.43 ;
      RECT 0.000000 300.000000 100.000000 358.128000 40.06 ;
      RECT 500.000000 200.000000 565.632000 300.000000 40.39 ;
      RECT 400.000000 200.000000 500.000000 300.000000 42.52 ;
      RECT 300.000000 200.000000 400.000000 300.000000 41.53 ;
      RECT 200.000000 200.000000 300.000000 300.000000 33.34 ;
      RECT 100.000000 200.000000 200.000000 300.000000 44.94 ;
      RECT 0.000000 200.000000 100.000000 300.000000 41.48 ;
      RECT 500.000000 100.000000 565.632000 200.000000 39.35 ;
      RECT 400.000000 100.000000 500.000000 200.000000 42.67 ;
      RECT 300.000000 100.000000 400.000000 200.000000 36.91 ;
      RECT 200.000000 100.000000 300.000000 200.000000 34.23 ;
      RECT 100.000000 100.000000 200.000000 200.000000 40.01 ;
      RECT 0.000000 100.000000 100.000000 200.000000 40.89 ;
      RECT 500.000000 0.000000 565.632000 100.000000 40.41 ;
      RECT 400.000000 0.000000 500.000000 100.000000 41.35 ;
      RECT 300.000000 0.000000 400.000000 100.000000 40.92 ;
      RECT 200.000000 0.000000 300.000000 100.000000 43.03 ;
      RECT 100.000000 0.000000 200.000000 100.000000 41.12 ;
      RECT 0.000000 0.000000 100.000000 100.000000 42.02 ;
      LAYER M2 ;
      RECT 500.000000 300.000000 565.632000 358.128000 39.38 ;
      RECT 400.000000 300.000000 500.000000 358.128000 48.11 ;
      RECT 300.000000 300.000000 400.000000 358.128000 40.33 ;
      RECT 200.000000 300.000000 300.000000 358.128000 58.59 ;
      RECT 100.000000 300.000000 200.000000 358.128000 40.24 ;
      RECT 0.000000 300.000000 100.000000 358.128000 40.35 ;
      RECT 500.000000 200.000000 565.632000 300.000000 40.83 ;
      RECT 400.000000 200.000000 500.000000 300.000000 44.44 ;
      RECT 300.000000 200.000000 400.000000 300.000000 40.22 ;
      RECT 200.000000 200.000000 300.000000 300.000000 27.41 ;
      RECT 100.000000 200.000000 200.000000 300.000000 47.89 ;
      RECT 0.000000 200.000000 100.000000 300.000000 41.41 ;
      RECT 500.000000 100.000000 565.632000 200.000000 39.12 ;
      RECT 400.000000 100.000000 500.000000 200.000000 44.75 ;
      RECT 300.000000 100.000000 400.000000 200.000000 34.01 ;
      RECT 200.000000 100.000000 300.000000 200.000000 28.47 ;
      RECT 100.000000 100.000000 200.000000 200.000000 40.02 ;
      RECT 0.000000 100.000000 100.000000 200.000000 40.69 ;
      RECT 500.000000 0.000000 565.632000 100.000000 40.71 ;
      RECT 400.000000 0.000000 500.000000 100.000000 41.89 ;
      RECT 300.000000 0.000000 400.000000 100.000000 41.57 ;
      RECT 200.000000 0.000000 300.000000 100.000000 44.63 ;
      RECT 100.000000 0.000000 200.000000 100.000000 42.34 ;
      RECT 0.000000 0.000000 100.000000 100.000000 41.98 ;
      LAYER M3 ;
      RECT 500.000000 300.000000 565.632000 358.128000 52.56 ;
      RECT 400.000000 300.000000 500.000000 358.128000 48.79 ;
      RECT 300.000000 300.000000 400.000000 358.128000 40.53 ;
      RECT 200.000000 300.000000 300.000000 358.128000 57.76 ;
      RECT 100.000000 300.000000 200.000000 358.128000 39.04 ;
      RECT 0.000000 300.000000 100.000000 358.128000 53.52 ;
      RECT 500.000000 200.000000 565.632000 300.000000 57.89 ;
      RECT 400.000000 200.000000 500.000000 300.000000 54.08 ;
      RECT 300.000000 200.000000 400.000000 300.000000 41.90 ;
      RECT 200.000000 200.000000 300.000000 300.000000 30.80 ;
      RECT 100.000000 200.000000 200.000000 300.000000 47.67 ;
      RECT 0.000000 200.000000 100.000000 300.000000 58.85 ;
      RECT 500.000000 100.000000 565.632000 200.000000 56.66 ;
      RECT 400.000000 100.000000 500.000000 200.000000 51.84 ;
      RECT 300.000000 100.000000 400.000000 200.000000 36.08 ;
      RECT 200.000000 100.000000 300.000000 200.000000 31.96 ;
      RECT 100.000000 100.000000 200.000000 200.000000 41.42 ;
      RECT 0.000000 100.000000 100.000000 200.000000 57.84 ;
      RECT 500.000000 0.000000 565.632000 100.000000 54.27 ;
      RECT 400.000000 0.000000 500.000000 100.000000 54.54 ;
      RECT 300.000000 0.000000 400.000000 100.000000 52.22 ;
      RECT 200.000000 0.000000 300.000000 100.000000 52.65 ;
      RECT 100.000000 0.000000 200.000000 100.000000 52.83 ;
      RECT 0.000000 0.000000 100.000000 100.000000 55.09 ;
      LAYER M4 ;
      RECT 500.000000 300.000000 565.632000 358.128000 16.36 ;
      RECT 400.000000 300.000000 500.000000 358.128000 28.46 ;
      RECT 300.000000 300.000000 400.000000 358.128000 25.22 ;
      RECT 200.000000 300.000000 300.000000 358.128000 34.71 ;
      RECT 100.000000 300.000000 200.000000 358.128000 26.57 ;
      RECT 0.000000 300.000000 100.000000 358.128000 16.80 ;
      RECT 500.000000 200.000000 565.632000 300.000000 15.03 ;
      RECT 400.000000 200.000000 500.000000 300.000000 24.42 ;
      RECT 300.000000 200.000000 400.000000 300.000000 27.43 ;
      RECT 200.000000 200.000000 300.000000 300.000000 24.05 ;
      RECT 100.000000 200.000000 200.000000 300.000000 29.73 ;
      RECT 0.000000 200.000000 100.000000 300.000000 15.50 ;
      RECT 500.000000 100.000000 565.632000 200.000000 15.88 ;
      RECT 400.000000 100.000000 500.000000 200.000000 26.77 ;
      RECT 300.000000 100.000000 400.000000 200.000000 26.54 ;
      RECT 200.000000 100.000000 300.000000 200.000000 26.69 ;
      RECT 100.000000 100.000000 200.000000 200.000000 26.40 ;
      RECT 0.000000 100.000000 100.000000 200.000000 16.26 ;
      RECT 500.000000 0.000000 565.632000 100.000000 16.24 ;
      RECT 400.000000 0.000000 500.000000 100.000000 16.78 ;
      RECT 300.000000 0.000000 400.000000 100.000000 15.29 ;
      RECT 200.000000 0.000000 300.000000 100.000000 18.29 ;
      RECT 100.000000 0.000000 200.000000 100.000000 17.08 ;
      RECT 0.000000 0.000000 100.000000 100.000000 16.60 ;
      LAYER M5 ;
      RECT 560.000000 340.000000 565.632000 358.128000 26.46 ;
      RECT 540.000000 340.000000 560.000000 358.128000 8.81 ;
      RECT 520.000000 340.000000 540.000000 358.128000 17.28 ;
      RECT 500.000000 340.000000 520.000000 358.128000 8.15 ;
      RECT 480.000000 340.000000 500.000000 358.128000 11.87 ;
      RECT 460.000000 340.000000 480.000000 358.128000 15.93 ;
      RECT 440.000000 340.000000 460.000000 358.128000 8.39 ;
      RECT 420.000000 340.000000 440.000000 358.128000 23.03 ;
      RECT 400.000000 340.000000 420.000000 358.128000 29.14 ;
      RECT 380.000000 340.000000 400.000000 358.128000 27.49 ;
      RECT 360.000000 340.000000 380.000000 358.128000 25.01 ;
      RECT 340.000000 340.000000 360.000000 358.128000 26.53 ;
      RECT 320.000000 340.000000 340.000000 358.128000 27.58 ;
      RECT 300.000000 340.000000 320.000000 358.128000 26.26 ;
      RECT 280.000000 340.000000 300.000000 358.128000 32.15 ;
      RECT 260.000000 340.000000 280.000000 358.128000 27.50 ;
      RECT 240.000000 340.000000 260.000000 358.128000 27.54 ;
      RECT 220.000000 340.000000 240.000000 358.128000 25.11 ;
      RECT 200.000000 340.000000 220.000000 358.128000 30.09 ;
      RECT 180.000000 340.000000 200.000000 358.128000 27.95 ;
      RECT 160.000000 340.000000 180.000000 358.128000 26.32 ;
      RECT 140.000000 340.000000 160.000000 358.128000 25.45 ;
      RECT 120.000000 340.000000 140.000000 358.128000 19.35 ;
      RECT 100.000000 340.000000 120.000000 358.128000 14.56 ;
      RECT 80.000000 340.000000 100.000000 358.128000 10.43 ;
      RECT 60.000000 340.000000 80.000000 358.128000 11.20 ;
      RECT 40.000000 340.000000 60.000000 358.128000 8.59 ;
      RECT 20.000000 340.000000 40.000000 358.128000 16.17 ;
      RECT 0.000000 340.000000 20.000000 358.128000 14.01 ;
      RECT 560.000000 320.000000 565.632000 340.000000 25.53 ;
      RECT 540.000000 320.000000 560.000000 340.000000 4.03 ;
      RECT 520.000000 320.000000 540.000000 340.000000 11.53 ;
      RECT 500.000000 320.000000 520.000000 340.000000 2.93 ;
      RECT 480.000000 320.000000 500.000000 340.000000 7.08 ;
      RECT 460.000000 320.000000 480.000000 340.000000 11.19 ;
      RECT 440.000000 320.000000 460.000000 340.000000 4.18 ;
      RECT 420.000000 320.000000 440.000000 340.000000 19.92 ;
      RECT 400.000000 320.000000 420.000000 340.000000 26.61 ;
      RECT 380.000000 320.000000 400.000000 340.000000 25.18 ;
      RECT 360.000000 320.000000 380.000000 340.000000 25.11 ;
      RECT 340.000000 320.000000 360.000000 340.000000 25.09 ;
      RECT 320.000000 320.000000 340.000000 340.000000 25.21 ;
      RECT 300.000000 320.000000 320.000000 340.000000 25.14 ;
      RECT 280.000000 320.000000 300.000000 340.000000 29.63 ;
      RECT 260.000000 320.000000 280.000000 340.000000 25.11 ;
      RECT 240.000000 320.000000 260.000000 340.000000 25.11 ;
      RECT 220.000000 320.000000 240.000000 340.000000 25.13 ;
      RECT 200.000000 320.000000 220.000000 340.000000 26.67 ;
      RECT 180.000000 320.000000 200.000000 340.000000 25.12 ;
      RECT 160.000000 320.000000 180.000000 340.000000 25.22 ;
      RECT 140.000000 320.000000 160.000000 340.000000 25.10 ;
      RECT 120.000000 320.000000 140.000000 340.000000 15.71 ;
      RECT 100.000000 320.000000 120.000000 340.000000 10.97 ;
      RECT 80.000000 320.000000 100.000000 340.000000 6.20 ;
      RECT 60.000000 320.000000 80.000000 340.000000 4.32 ;
      RECT 40.000000 320.000000 60.000000 340.000000 3.10 ;
      RECT 20.000000 320.000000 40.000000 340.000000 12.44 ;
      RECT 0.000000 320.000000 20.000000 340.000000 9.96 ;
      RECT 560.000000 300.000000 565.632000 320.000000 25.63 ;
      RECT 540.000000 300.000000 560.000000 320.000000 5.72 ;
      RECT 520.000000 300.000000 540.000000 320.000000 13.93 ;
      RECT 500.000000 300.000000 520.000000 320.000000 4.13 ;
      RECT 480.000000 300.000000 500.000000 320.000000 7.67 ;
      RECT 460.000000 300.000000 480.000000 320.000000 13.14 ;
      RECT 440.000000 300.000000 460.000000 320.000000 5.92 ;
      RECT 420.000000 300.000000 440.000000 320.000000 22.51 ;
      RECT 400.000000 300.000000 420.000000 320.000000 28.01 ;
      RECT 380.000000 300.000000 400.000000 320.000000 25.05 ;
      RECT 360.000000 300.000000 380.000000 320.000000 25.12 ;
      RECT 340.000000 300.000000 360.000000 320.000000 25.14 ;
      RECT 320.000000 300.000000 340.000000 320.000000 25.06 ;
      RECT 300.000000 300.000000 320.000000 320.000000 25.09 ;
      RECT 280.000000 300.000000 300.000000 320.000000 33.72 ;
      RECT 260.000000 300.000000 280.000000 320.000000 25.15 ;
      RECT 240.000000 300.000000 260.000000 320.000000 25.05 ;
      RECT 220.000000 300.000000 240.000000 320.000000 25.11 ;
      RECT 200.000000 300.000000 220.000000 320.000000 27.69 ;
      RECT 180.000000 300.000000 200.000000 320.000000 25.07 ;
      RECT 160.000000 300.000000 180.000000 320.000000 25.08 ;
      RECT 140.000000 300.000000 160.000000 320.000000 25.55 ;
      RECT 120.000000 300.000000 140.000000 320.000000 17.69 ;
      RECT 100.000000 300.000000 120.000000 320.000000 12.11 ;
      RECT 80.000000 300.000000 100.000000 320.000000 6.94 ;
      RECT 60.000000 300.000000 80.000000 320.000000 6.70 ;
      RECT 40.000000 300.000000 60.000000 320.000000 3.78 ;
      RECT 20.000000 300.000000 40.000000 320.000000 14.36 ;
      RECT 0.000000 300.000000 20.000000 320.000000 10.87 ;
      RECT 560.000000 280.000000 565.632000 300.000000 25.63 ;
      RECT 540.000000 280.000000 560.000000 300.000000 4.22 ;
      RECT 520.000000 280.000000 540.000000 300.000000 11.85 ;
      RECT 500.000000 280.000000 520.000000 300.000000 3.19 ;
      RECT 480.000000 280.000000 500.000000 300.000000 6.31 ;
      RECT 460.000000 280.000000 480.000000 300.000000 11.28 ;
      RECT 440.000000 280.000000 460.000000 300.000000 4.31 ;
      RECT 420.000000 280.000000 440.000000 300.000000 22.26 ;
      RECT 400.000000 280.000000 420.000000 300.000000 33.55 ;
      RECT 380.000000 280.000000 400.000000 300.000000 31.58 ;
      RECT 360.000000 280.000000 380.000000 300.000000 30.47 ;
      RECT 340.000000 280.000000 360.000000 300.000000 33.83 ;
      RECT 320.000000 280.000000 340.000000 300.000000 33.38 ;
      RECT 300.000000 280.000000 320.000000 300.000000 32.15 ;
      RECT 280.000000 280.000000 300.000000 300.000000 38.45 ;
      RECT 260.000000 280.000000 280.000000 300.000000 32.44 ;
      RECT 240.000000 280.000000 260.000000 300.000000 27.67 ;
      RECT 220.000000 280.000000 240.000000 300.000000 32.52 ;
      RECT 200.000000 280.000000 220.000000 300.000000 37.20 ;
      RECT 180.000000 280.000000 200.000000 300.000000 29.17 ;
      RECT 160.000000 280.000000 180.000000 300.000000 32.92 ;
      RECT 140.000000 280.000000 160.000000 300.000000 35.88 ;
      RECT 120.000000 280.000000 140.000000 300.000000 11.89 ;
      RECT 100.000000 280.000000 120.000000 300.000000 9.89 ;
      RECT 80.000000 280.000000 100.000000 300.000000 6.13 ;
      RECT 60.000000 280.000000 80.000000 300.000000 4.39 ;
      RECT 40.000000 280.000000 60.000000 300.000000 2.91 ;
      RECT 20.000000 280.000000 40.000000 300.000000 12.32 ;
      RECT 0.000000 280.000000 20.000000 300.000000 10.18 ;
      RECT 560.000000 260.000000 565.632000 280.000000 25.65 ;
      RECT 540.000000 260.000000 560.000000 280.000000 3.66 ;
      RECT 520.000000 260.000000 540.000000 280.000000 13.72 ;
      RECT 500.000000 260.000000 520.000000 280.000000 3.49 ;
      RECT 480.000000 260.000000 500.000000 280.000000 6.89 ;
      RECT 460.000000 260.000000 480.000000 280.000000 12.06 ;
      RECT 440.000000 260.000000 460.000000 280.000000 4.24 ;
      RECT 420.000000 260.000000 440.000000 280.000000 22.51 ;
      RECT 400.000000 260.000000 420.000000 280.000000 28.55 ;
      RECT 380.000000 260.000000 400.000000 280.000000 25.10 ;
      RECT 360.000000 260.000000 380.000000 280.000000 25.13 ;
      RECT 340.000000 260.000000 360.000000 280.000000 25.53 ;
      RECT 320.000000 260.000000 340.000000 280.000000 25.29 ;
      RECT 300.000000 260.000000 320.000000 280.000000 25.32 ;
      RECT 280.000000 260.000000 300.000000 280.000000 32.73 ;
      RECT 260.000000 260.000000 280.000000 280.000000 24.03 ;
      RECT 240.000000 260.000000 260.000000 280.000000 22.07 ;
      RECT 220.000000 260.000000 240.000000 280.000000 22.67 ;
      RECT 200.000000 260.000000 220.000000 280.000000 22.07 ;
      RECT 180.000000 260.000000 200.000000 280.000000 25.88 ;
      RECT 160.000000 260.000000 180.000000 280.000000 25.07 ;
      RECT 140.000000 260.000000 160.000000 280.000000 27.70 ;
      RECT 120.000000 260.000000 140.000000 280.000000 10.93 ;
      RECT 100.000000 260.000000 120.000000 280.000000 10.05 ;
      RECT 80.000000 260.000000 100.000000 280.000000 6.40 ;
      RECT 60.000000 260.000000 80.000000 280.000000 6.52 ;
      RECT 40.000000 260.000000 60.000000 280.000000 3.36 ;
      RECT 20.000000 260.000000 40.000000 280.000000 13.92 ;
      RECT 0.000000 260.000000 20.000000 280.000000 10.13 ;
      RECT 560.000000 240.000000 565.632000 260.000000 25.56 ;
      RECT 540.000000 240.000000 560.000000 260.000000 3.23 ;
      RECT 520.000000 240.000000 540.000000 260.000000 11.79 ;
      RECT 500.000000 240.000000 520.000000 260.000000 3.17 ;
      RECT 480.000000 240.000000 500.000000 260.000000 6.38 ;
      RECT 460.000000 240.000000 480.000000 260.000000 10.12 ;
      RECT 440.000000 240.000000 460.000000 260.000000 4.32 ;
      RECT 420.000000 240.000000 440.000000 260.000000 23.42 ;
      RECT 400.000000 240.000000 420.000000 260.000000 28.64 ;
      RECT 380.000000 240.000000 400.000000 260.000000 25.07 ;
      RECT 360.000000 240.000000 380.000000 260.000000 25.09 ;
      RECT 340.000000 240.000000 360.000000 260.000000 25.28 ;
      RECT 320.000000 240.000000 340.000000 260.000000 25.71 ;
      RECT 300.000000 240.000000 320.000000 260.000000 25.17 ;
      RECT 280.000000 240.000000 300.000000 260.000000 32.62 ;
      RECT 260.000000 240.000000 280.000000 260.000000 25.88 ;
      RECT 240.000000 240.000000 260.000000 260.000000 23.53 ;
      RECT 220.000000 240.000000 240.000000 260.000000 22.53 ;
      RECT 200.000000 240.000000 220.000000 260.000000 29.79 ;
      RECT 180.000000 240.000000 200.000000 260.000000 25.69 ;
      RECT 160.000000 240.000000 180.000000 260.000000 25.15 ;
      RECT 140.000000 240.000000 160.000000 260.000000 28.18 ;
      RECT 120.000000 240.000000 140.000000 260.000000 10.88 ;
      RECT 100.000000 240.000000 120.000000 260.000000 8.73 ;
      RECT 80.000000 240.000000 100.000000 260.000000 5.89 ;
      RECT 60.000000 240.000000 80.000000 260.000000 4.32 ;
      RECT 40.000000 240.000000 60.000000 260.000000 2.75 ;
      RECT 20.000000 240.000000 40.000000 260.000000 12.72 ;
      RECT 0.000000 240.000000 20.000000 260.000000 10.04 ;
      RECT 560.000000 220.000000 565.632000 240.000000 25.56 ;
      RECT 540.000000 220.000000 560.000000 240.000000 5.05 ;
      RECT 520.000000 220.000000 540.000000 240.000000 13.77 ;
      RECT 500.000000 220.000000 520.000000 240.000000 4.15 ;
      RECT 480.000000 220.000000 500.000000 240.000000 7.30 ;
      RECT 460.000000 220.000000 480.000000 240.000000 12.37 ;
      RECT 440.000000 220.000000 460.000000 240.000000 6.94 ;
      RECT 420.000000 220.000000 440.000000 240.000000 21.22 ;
      RECT 400.000000 220.000000 420.000000 240.000000 27.78 ;
      RECT 380.000000 220.000000 400.000000 240.000000 25.13 ;
      RECT 360.000000 220.000000 380.000000 240.000000 25.10 ;
      RECT 340.000000 220.000000 360.000000 240.000000 25.06 ;
      RECT 320.000000 220.000000 340.000000 240.000000 25.50 ;
      RECT 300.000000 220.000000 320.000000 240.000000 24.05 ;
      RECT 280.000000 220.000000 300.000000 240.000000 27.53 ;
      RECT 260.000000 220.000000 280.000000 240.000000 24.80 ;
      RECT 240.000000 220.000000 260.000000 240.000000 22.23 ;
      RECT 220.000000 220.000000 240.000000 240.000000 25.13 ;
      RECT 200.000000 220.000000 220.000000 240.000000 27.65 ;
      RECT 180.000000 220.000000 200.000000 240.000000 25.08 ;
      RECT 160.000000 220.000000 180.000000 240.000000 25.11 ;
      RECT 140.000000 220.000000 160.000000 240.000000 26.70 ;
      RECT 120.000000 220.000000 140.000000 240.000000 15.55 ;
      RECT 100.000000 220.000000 120.000000 240.000000 9.46 ;
      RECT 80.000000 220.000000 100.000000 240.000000 6.52 ;
      RECT 60.000000 220.000000 80.000000 240.000000 6.55 ;
      RECT 40.000000 220.000000 60.000000 240.000000 3.28 ;
      RECT 20.000000 220.000000 40.000000 240.000000 14.68 ;
      RECT 0.000000 220.000000 20.000000 240.000000 10.82 ;
      RECT 560.000000 200.000000 565.632000 220.000000 25.59 ;
      RECT 540.000000 200.000000 560.000000 220.000000 3.41 ;
      RECT 520.000000 200.000000 540.000000 220.000000 11.98 ;
      RECT 500.000000 200.000000 520.000000 220.000000 2.40 ;
      RECT 480.000000 200.000000 500.000000 220.000000 5.86 ;
      RECT 460.000000 200.000000 480.000000 220.000000 10.49 ;
      RECT 440.000000 200.000000 460.000000 220.000000 6.07 ;
      RECT 420.000000 200.000000 440.000000 220.000000 23.40 ;
      RECT 400.000000 200.000000 420.000000 220.000000 32.16 ;
      RECT 380.000000 200.000000 400.000000 220.000000 29.61 ;
      RECT 360.000000 200.000000 380.000000 220.000000 28.29 ;
      RECT 340.000000 200.000000 360.000000 220.000000 30.19 ;
      RECT 320.000000 200.000000 340.000000 220.000000 27.10 ;
      RECT 300.000000 200.000000 320.000000 220.000000 26.71 ;
      RECT 280.000000 200.000000 300.000000 220.000000 31.08 ;
      RECT 260.000000 200.000000 280.000000 220.000000 26.53 ;
      RECT 240.000000 200.000000 260.000000 220.000000 29.64 ;
      RECT 220.000000 200.000000 240.000000 220.000000 28.84 ;
      RECT 200.000000 200.000000 220.000000 220.000000 31.85 ;
      RECT 180.000000 200.000000 200.000000 220.000000 27.42 ;
      RECT 160.000000 200.000000 180.000000 220.000000 29.72 ;
      RECT 140.000000 200.000000 160.000000 220.000000 31.79 ;
      RECT 120.000000 200.000000 140.000000 220.000000 15.97 ;
      RECT 100.000000 200.000000 120.000000 220.000000 7.89 ;
      RECT 80.000000 200.000000 100.000000 220.000000 5.44 ;
      RECT 60.000000 200.000000 80.000000 220.000000 4.33 ;
      RECT 40.000000 200.000000 60.000000 220.000000 1.98 ;
      RECT 20.000000 200.000000 40.000000 220.000000 12.88 ;
      RECT 0.000000 200.000000 20.000000 220.000000 9.82 ;
      RECT 560.000000 180.000000 565.632000 200.000000 26.22 ;
      RECT 540.000000 180.000000 560.000000 200.000000 1.95 ;
      RECT 520.000000 180.000000 540.000000 200.000000 11.48 ;
      RECT 500.000000 180.000000 520.000000 200.000000 1.89 ;
      RECT 480.000000 180.000000 500.000000 200.000000 5.02 ;
      RECT 460.000000 180.000000 480.000000 200.000000 9.22 ;
      RECT 440.000000 180.000000 460.000000 200.000000 3.53 ;
      RECT 420.000000 180.000000 440.000000 200.000000 21.73 ;
      RECT 400.000000 180.000000 420.000000 200.000000 25.28 ;
      RECT 380.000000 180.000000 400.000000 200.000000 26.32 ;
      RECT 360.000000 180.000000 380.000000 200.000000 25.11 ;
      RECT 340.000000 180.000000 360.000000 200.000000 25.09 ;
      RECT 320.000000 180.000000 340.000000 200.000000 25.06 ;
      RECT 300.000000 180.000000 320.000000 200.000000 25.17 ;
      RECT 280.000000 180.000000 300.000000 200.000000 24.17 ;
      RECT 260.000000 180.000000 280.000000 200.000000 23.71 ;
      RECT 240.000000 180.000000 260.000000 200.000000 25.21 ;
      RECT 220.000000 180.000000 240.000000 200.000000 25.02 ;
      RECT 200.000000 180.000000 220.000000 200.000000 25.09 ;
      RECT 180.000000 180.000000 200.000000 200.000000 26.31 ;
      RECT 160.000000 180.000000 180.000000 200.000000 25.07 ;
      RECT 140.000000 180.000000 160.000000 200.000000 26.00 ;
      RECT 120.000000 180.000000 140.000000 200.000000 13.47 ;
      RECT 100.000000 180.000000 120.000000 200.000000 6.41 ;
      RECT 80.000000 180.000000 100.000000 200.000000 5.61 ;
      RECT 60.000000 180.000000 80.000000 200.000000 4.28 ;
      RECT 40.000000 180.000000 60.000000 200.000000 1.90 ;
      RECT 20.000000 180.000000 40.000000 200.000000 12.37 ;
      RECT 0.000000 180.000000 20.000000 200.000000 8.76 ;
      RECT 560.000000 160.000000 565.632000 180.000000 25.57 ;
      RECT 540.000000 160.000000 560.000000 180.000000 3.65 ;
      RECT 520.000000 160.000000 540.000000 180.000000 13.60 ;
      RECT 500.000000 160.000000 520.000000 180.000000 3.84 ;
      RECT 480.000000 160.000000 500.000000 180.000000 7.11 ;
      RECT 460.000000 160.000000 480.000000 180.000000 11.11 ;
      RECT 440.000000 160.000000 460.000000 180.000000 5.09 ;
      RECT 420.000000 160.000000 440.000000 180.000000 23.36 ;
      RECT 400.000000 160.000000 420.000000 180.000000 27.90 ;
      RECT 380.000000 160.000000 400.000000 180.000000 25.04 ;
      RECT 360.000000 160.000000 380.000000 180.000000 25.14 ;
      RECT 340.000000 160.000000 360.000000 180.000000 25.38 ;
      RECT 320.000000 160.000000 340.000000 180.000000 25.83 ;
      RECT 300.000000 160.000000 320.000000 180.000000 24.84 ;
      RECT 280.000000 160.000000 300.000000 180.000000 27.90 ;
      RECT 260.000000 160.000000 280.000000 180.000000 25.53 ;
      RECT 240.000000 160.000000 260.000000 180.000000 25.49 ;
      RECT 220.000000 160.000000 240.000000 180.000000 25.27 ;
      RECT 200.000000 160.000000 220.000000 180.000000 31.75 ;
      RECT 180.000000 160.000000 200.000000 180.000000 25.67 ;
      RECT 160.000000 160.000000 180.000000 180.000000 25.11 ;
      RECT 140.000000 160.000000 160.000000 180.000000 26.76 ;
      RECT 120.000000 160.000000 140.000000 180.000000 13.40 ;
      RECT 100.000000 160.000000 120.000000 180.000000 8.61 ;
      RECT 80.000000 160.000000 100.000000 180.000000 7.00 ;
      RECT 60.000000 160.000000 80.000000 180.000000 6.53 ;
      RECT 40.000000 160.000000 60.000000 180.000000 4.01 ;
      RECT 20.000000 160.000000 40.000000 180.000000 13.78 ;
      RECT 0.000000 160.000000 20.000000 180.000000 10.85 ;
      RECT 560.000000 140.000000 565.632000 160.000000 25.38 ;
      RECT 540.000000 140.000000 560.000000 160.000000 4.11 ;
      RECT 520.000000 140.000000 540.000000 160.000000 11.15 ;
      RECT 500.000000 140.000000 520.000000 160.000000 3.57 ;
      RECT 480.000000 140.000000 500.000000 160.000000 6.70 ;
      RECT 460.000000 140.000000 480.000000 160.000000 9.13 ;
      RECT 440.000000 140.000000 460.000000 160.000000 6.41 ;
      RECT 420.000000 140.000000 440.000000 160.000000 21.76 ;
      RECT 400.000000 140.000000 420.000000 160.000000 27.85 ;
      RECT 380.000000 140.000000 400.000000 160.000000 25.11 ;
      RECT 360.000000 140.000000 380.000000 160.000000 25.08 ;
      RECT 340.000000 140.000000 360.000000 160.000000 25.16 ;
      RECT 320.000000 140.000000 340.000000 160.000000 25.79 ;
      RECT 300.000000 140.000000 320.000000 160.000000 24.80 ;
      RECT 280.000000 140.000000 300.000000 160.000000 27.60 ;
      RECT 260.000000 140.000000 280.000000 160.000000 24.12 ;
      RECT 240.000000 140.000000 260.000000 160.000000 25.23 ;
      RECT 220.000000 140.000000 240.000000 160.000000 25.83 ;
      RECT 200.000000 140.000000 220.000000 160.000000 22.81 ;
      RECT 180.000000 140.000000 200.000000 160.000000 26.63 ;
      RECT 160.000000 140.000000 180.000000 160.000000 25.16 ;
      RECT 140.000000 140.000000 160.000000 160.000000 26.53 ;
      RECT 120.000000 140.000000 140.000000 160.000000 13.37 ;
      RECT 100.000000 140.000000 120.000000 160.000000 8.95 ;
      RECT 80.000000 140.000000 100.000000 160.000000 6.03 ;
      RECT 60.000000 140.000000 80.000000 160.000000 4.30 ;
      RECT 40.000000 140.000000 60.000000 160.000000 3.96 ;
      RECT 20.000000 140.000000 40.000000 160.000000 11.32 ;
      RECT 0.000000 140.000000 20.000000 160.000000 9.87 ;
      RECT 560.000000 120.000000 565.632000 140.000000 25.58 ;
      RECT 540.000000 120.000000 560.000000 140.000000 5.38 ;
      RECT 520.000000 120.000000 540.000000 140.000000 13.65 ;
      RECT 500.000000 120.000000 520.000000 140.000000 5.09 ;
      RECT 480.000000 120.000000 500.000000 140.000000 7.85 ;
      RECT 460.000000 120.000000 480.000000 140.000000 9.46 ;
      RECT 440.000000 120.000000 460.000000 140.000000 7.08 ;
      RECT 420.000000 120.000000 440.000000 140.000000 22.67 ;
      RECT 400.000000 120.000000 420.000000 140.000000 28.14 ;
      RECT 380.000000 120.000000 400.000000 140.000000 25.02 ;
      RECT 360.000000 120.000000 380.000000 140.000000 25.08 ;
      RECT 340.000000 120.000000 360.000000 140.000000 25.03 ;
      RECT 320.000000 120.000000 340.000000 140.000000 25.04 ;
      RECT 300.000000 120.000000 320.000000 140.000000 25.05 ;
      RECT 280.000000 120.000000 300.000000 140.000000 23.78 ;
      RECT 260.000000 120.000000 280.000000 140.000000 22.15 ;
      RECT 240.000000 120.000000 260.000000 140.000000 23.29 ;
      RECT 220.000000 120.000000 240.000000 140.000000 25.83 ;
      RECT 200.000000 120.000000 220.000000 140.000000 25.23 ;
      RECT 180.000000 120.000000 200.000000 140.000000 25.90 ;
      RECT 160.000000 120.000000 180.000000 140.000000 25.11 ;
      RECT 140.000000 120.000000 160.000000 140.000000 25.95 ;
      RECT 120.000000 120.000000 140.000000 140.000000 14.29 ;
      RECT 100.000000 120.000000 120.000000 140.000000 10.10 ;
      RECT 80.000000 120.000000 100.000000 140.000000 6.36 ;
      RECT 60.000000 120.000000 80.000000 140.000000 6.58 ;
      RECT 40.000000 120.000000 60.000000 140.000000 4.72 ;
      RECT 20.000000 120.000000 40.000000 140.000000 13.32 ;
      RECT 0.000000 120.000000 20.000000 140.000000 10.85 ;
      RECT 560.000000 100.000000 565.632000 120.000000 25.59 ;
      RECT 540.000000 100.000000 560.000000 120.000000 3.74 ;
      RECT 520.000000 100.000000 540.000000 120.000000 12.01 ;
      RECT 500.000000 100.000000 520.000000 120.000000 3.80 ;
      RECT 480.000000 100.000000 500.000000 120.000000 7.30 ;
      RECT 460.000000 100.000000 480.000000 120.000000 7.78 ;
      RECT 440.000000 100.000000 460.000000 120.000000 5.64 ;
      RECT 420.000000 100.000000 440.000000 120.000000 19.45 ;
      RECT 400.000000 100.000000 420.000000 120.000000 28.46 ;
      RECT 380.000000 100.000000 400.000000 120.000000 25.07 ;
      RECT 360.000000 100.000000 380.000000 120.000000 25.07 ;
      RECT 340.000000 100.000000 360.000000 120.000000 25.04 ;
      RECT 320.000000 100.000000 340.000000 120.000000 25.15 ;
      RECT 300.000000 100.000000 320.000000 120.000000 25.81 ;
      RECT 280.000000 100.000000 300.000000 120.000000 24.71 ;
      RECT 260.000000 100.000000 280.000000 120.000000 25.42 ;
      RECT 240.000000 100.000000 260.000000 120.000000 25.22 ;
      RECT 220.000000 100.000000 240.000000 120.000000 24.92 ;
      RECT 200.000000 100.000000 220.000000 120.000000 28.33 ;
      RECT 180.000000 100.000000 200.000000 120.000000 25.07 ;
      RECT 160.000000 100.000000 180.000000 120.000000 25.10 ;
      RECT 140.000000 100.000000 160.000000 120.000000 26.87 ;
      RECT 120.000000 100.000000 140.000000 120.000000 13.57 ;
      RECT 100.000000 100.000000 120.000000 120.000000 9.85 ;
      RECT 80.000000 100.000000 100.000000 120.000000 6.21 ;
      RECT 60.000000 100.000000 80.000000 120.000000 4.31 ;
      RECT 40.000000 100.000000 60.000000 120.000000 2.88 ;
      RECT 20.000000 100.000000 40.000000 120.000000 11.77 ;
      RECT 0.000000 100.000000 20.000000 120.000000 10.04 ;
      RECT 560.000000 80.000000 565.632000 100.000000 26.18 ;
      RECT 540.000000 80.000000 560.000000 100.000000 3.90 ;
      RECT 520.000000 80.000000 540.000000 100.000000 13.89 ;
      RECT 500.000000 80.000000 520.000000 100.000000 4.54 ;
      RECT 480.000000 80.000000 500.000000 100.000000 7.84 ;
      RECT 460.000000 80.000000 480.000000 100.000000 8.65 ;
      RECT 440.000000 80.000000 460.000000 100.000000 6.91 ;
      RECT 420.000000 80.000000 440.000000 100.000000 21.07 ;
      RECT 400.000000 80.000000 420.000000 100.000000 28.30 ;
      RECT 380.000000 80.000000 400.000000 100.000000 27.81 ;
      RECT 360.000000 80.000000 380.000000 100.000000 25.96 ;
      RECT 340.000000 80.000000 360.000000 100.000000 27.87 ;
      RECT 320.000000 80.000000 340.000000 100.000000 29.22 ;
      RECT 300.000000 80.000000 320.000000 100.000000 27.99 ;
      RECT 280.000000 80.000000 300.000000 100.000000 21.72 ;
      RECT 260.000000 80.000000 280.000000 100.000000 25.24 ;
      RECT 240.000000 80.000000 260.000000 100.000000 25.13 ;
      RECT 220.000000 80.000000 240.000000 100.000000 30.00 ;
      RECT 200.000000 80.000000 220.000000 100.000000 37.95 ;
      RECT 180.000000 80.000000 200.000000 100.000000 25.95 ;
      RECT 160.000000 80.000000 180.000000 100.000000 27.19 ;
      RECT 140.000000 80.000000 160.000000 100.000000 30.88 ;
      RECT 120.000000 80.000000 140.000000 100.000000 18.71 ;
      RECT 100.000000 80.000000 120.000000 100.000000 9.41 ;
      RECT 80.000000 80.000000 100.000000 100.000000 6.90 ;
      RECT 60.000000 80.000000 80.000000 100.000000 6.59 ;
      RECT 40.000000 80.000000 60.000000 100.000000 3.31 ;
      RECT 20.000000 80.000000 40.000000 100.000000 14.14 ;
      RECT 0.000000 80.000000 20.000000 100.000000 10.01 ;
      RECT 560.000000 60.000000 565.632000 80.000000 25.56 ;
      RECT 540.000000 60.000000 560.000000 80.000000 3.58 ;
      RECT 520.000000 60.000000 540.000000 80.000000 11.82 ;
      RECT 500.000000 60.000000 520.000000 80.000000 4.14 ;
      RECT 480.000000 60.000000 500.000000 80.000000 7.42 ;
      RECT 460.000000 60.000000 480.000000 80.000000 7.89 ;
      RECT 440.000000 60.000000 460.000000 80.000000 7.03 ;
      RECT 420.000000 60.000000 440.000000 80.000000 13.29 ;
      RECT 400.000000 60.000000 420.000000 80.000000 8.77 ;
      RECT 380.000000 60.000000 400.000000 80.000000 11.51 ;
      RECT 360.000000 60.000000 380.000000 80.000000 6.40 ;
      RECT 340.000000 60.000000 360.000000 80.000000 8.89 ;
      RECT 320.000000 60.000000 340.000000 80.000000 10.55 ;
      RECT 300.000000 60.000000 320.000000 80.000000 12.47 ;
      RECT 280.000000 60.000000 300.000000 80.000000 11.56 ;
      RECT 260.000000 60.000000 280.000000 80.000000 6.65 ;
      RECT 240.000000 60.000000 260.000000 80.000000 8.27 ;
      RECT 220.000000 60.000000 240.000000 80.000000 29.74 ;
      RECT 200.000000 60.000000 220.000000 80.000000 31.75 ;
      RECT 180.000000 60.000000 200.000000 80.000000 10.67 ;
      RECT 160.000000 60.000000 180.000000 80.000000 4.25 ;
      RECT 140.000000 60.000000 160.000000 80.000000 8.44 ;
      RECT 120.000000 60.000000 140.000000 80.000000 15.20 ;
      RECT 100.000000 60.000000 120.000000 80.000000 8.95 ;
      RECT 80.000000 60.000000 100.000000 80.000000 6.34 ;
      RECT 60.000000 60.000000 80.000000 80.000000 4.31 ;
      RECT 40.000000 60.000000 60.000000 80.000000 3.02 ;
      RECT 20.000000 60.000000 40.000000 80.000000 11.95 ;
      RECT 0.000000 60.000000 20.000000 80.000000 10.21 ;
      RECT 560.000000 40.000000 565.632000 60.000000 25.56 ;
      RECT 540.000000 40.000000 560.000000 60.000000 4.66 ;
      RECT 520.000000 40.000000 540.000000 60.000000 13.03 ;
      RECT 500.000000 40.000000 520.000000 60.000000 4.56 ;
      RECT 480.000000 40.000000 500.000000 60.000000 8.58 ;
      RECT 460.000000 40.000000 480.000000 60.000000 12.14 ;
      RECT 440.000000 40.000000 460.000000 60.000000 6.78 ;
      RECT 420.000000 40.000000 440.000000 60.000000 12.87 ;
      RECT 400.000000 40.000000 420.000000 60.000000 7.31 ;
      RECT 380.000000 40.000000 400.000000 60.000000 11.42 ;
      RECT 360.000000 40.000000 380.000000 60.000000 8.67 ;
      RECT 340.000000 40.000000 360.000000 60.000000 8.36 ;
      RECT 320.000000 40.000000 340.000000 60.000000 10.74 ;
      RECT 300.000000 40.000000 320.000000 60.000000 13.28 ;
      RECT 280.000000 40.000000 300.000000 60.000000 10.59 ;
      RECT 260.000000 40.000000 280.000000 60.000000 8.04 ;
      RECT 240.000000 40.000000 260.000000 60.000000 7.62 ;
      RECT 220.000000 40.000000 240.000000 60.000000 15.89 ;
      RECT 200.000000 40.000000 220.000000 60.000000 17.37 ;
      RECT 180.000000 40.000000 200.000000 60.000000 10.14 ;
      RECT 160.000000 40.000000 180.000000 60.000000 6.12 ;
      RECT 140.000000 40.000000 160.000000 60.000000 8.30 ;
      RECT 120.000000 40.000000 140.000000 60.000000 14.75 ;
      RECT 100.000000 40.000000 120.000000 60.000000 10.19 ;
      RECT 80.000000 40.000000 100.000000 60.000000 6.53 ;
      RECT 60.000000 40.000000 80.000000 60.000000 6.56 ;
      RECT 40.000000 40.000000 60.000000 60.000000 4.25 ;
      RECT 20.000000 40.000000 40.000000 60.000000 13.01 ;
      RECT 0.000000 40.000000 20.000000 60.000000 10.69 ;
      RECT 560.000000 20.000000 565.632000 40.000000 25.61 ;
      RECT 540.000000 20.000000 560.000000 40.000000 3.82 ;
      RECT 520.000000 20.000000 540.000000 40.000000 11.95 ;
      RECT 500.000000 20.000000 520.000000 40.000000 3.45 ;
      RECT 480.000000 20.000000 500.000000 40.000000 7.45 ;
      RECT 460.000000 20.000000 480.000000 40.000000 11.24 ;
      RECT 440.000000 20.000000 460.000000 40.000000 4.81 ;
      RECT 420.000000 20.000000 440.000000 40.000000 9.58 ;
      RECT 400.000000 20.000000 420.000000 40.000000 5.44 ;
      RECT 380.000000 20.000000 400.000000 40.000000 9.45 ;
      RECT 360.000000 20.000000 380.000000 40.000000 5.90 ;
      RECT 340.000000 20.000000 360.000000 40.000000 5.91 ;
      RECT 320.000000 20.000000 340.000000 40.000000 7.99 ;
      RECT 300.000000 20.000000 320.000000 40.000000 12.03 ;
      RECT 280.000000 20.000000 300.000000 40.000000 6.89 ;
      RECT 260.000000 20.000000 280.000000 40.000000 5.99 ;
      RECT 240.000000 20.000000 260.000000 40.000000 5.23 ;
      RECT 220.000000 20.000000 240.000000 40.000000 14.53 ;
      RECT 200.000000 20.000000 220.000000 40.000000 16.82 ;
      RECT 180.000000 20.000000 200.000000 40.000000 7.12 ;
      RECT 160.000000 20.000000 180.000000 40.000000 3.95 ;
      RECT 140.000000 20.000000 160.000000 40.000000 6.16 ;
      RECT 120.000000 20.000000 140.000000 40.000000 12.40 ;
      RECT 100.000000 20.000000 120.000000 40.000000 11.08 ;
      RECT 80.000000 20.000000 100.000000 40.000000 6.00 ;
      RECT 60.000000 20.000000 80.000000 40.000000 4.33 ;
      RECT 40.000000 20.000000 60.000000 40.000000 3.20 ;
      RECT 20.000000 20.000000 40.000000 40.000000 10.89 ;
      RECT 0.000000 20.000000 20.000000 40.000000 9.96 ;
      RECT 560.000000 0.000000 565.632000 20.000000 25.58 ;
      RECT 540.000000 0.000000 560.000000 20.000000 7.59 ;
      RECT 520.000000 0.000000 540.000000 20.000000 16.81 ;
      RECT 500.000000 0.000000 520.000000 20.000000 7.33 ;
      RECT 480.000000 0.000000 500.000000 20.000000 10.63 ;
      RECT 460.000000 0.000000 480.000000 20.000000 16.19 ;
      RECT 440.000000 0.000000 460.000000 20.000000 8.26 ;
      RECT 420.000000 0.000000 440.000000 20.000000 14.57 ;
      RECT 400.000000 0.000000 420.000000 20.000000 8.80 ;
      RECT 380.000000 0.000000 400.000000 20.000000 11.47 ;
      RECT 360.000000 0.000000 380.000000 20.000000 10.81 ;
      RECT 340.000000 0.000000 360.000000 20.000000 8.61 ;
      RECT 320.000000 0.000000 340.000000 20.000000 10.47 ;
      RECT 300.000000 0.000000 320.000000 20.000000 15.17 ;
      RECT 280.000000 0.000000 300.000000 20.000000 8.70 ;
      RECT 260.000000 0.000000 280.000000 20.000000 10.74 ;
      RECT 240.000000 0.000000 260.000000 20.000000 8.13 ;
      RECT 220.000000 0.000000 240.000000 20.000000 16.35 ;
      RECT 200.000000 0.000000 220.000000 20.000000 18.22 ;
      RECT 180.000000 0.000000 200.000000 20.000000 8.73 ;
      RECT 160.000000 0.000000 180.000000 20.000000 9.68 ;
      RECT 140.000000 0.000000 160.000000 20.000000 8.86 ;
      RECT 120.000000 0.000000 140.000000 20.000000 15.97 ;
      RECT 100.000000 0.000000 120.000000 20.000000 14.36 ;
      RECT 80.000000 0.000000 100.000000 20.000000 9.14 ;
      RECT 60.000000 0.000000 80.000000 20.000000 10.25 ;
      RECT 40.000000 0.000000 60.000000 20.000000 7.74 ;
      RECT 20.000000 0.000000 40.000000 20.000000 17.38 ;
      RECT 0.000000 0.000000 20.000000 20.000000 13.64 ;
      LAYER M6 ;
      RECT 500.000000 300.000000 565.632000 358.128000 38.82 ;
      RECT 400.000000 300.000000 500.000000 358.128000 50.00 ;
      RECT 300.000000 300.000000 400.000000 358.128000 40.25 ;
      RECT 200.000000 300.000000 300.000000 358.128000 53.27 ;
      RECT 100.000000 300.000000 200.000000 358.128000 40.34 ;
      RECT 0.000000 300.000000 100.000000 358.128000 48.58 ;
      RECT 500.000000 200.000000 565.632000 300.000000 51.11 ;
      RECT 400.000000 200.000000 500.000000 300.000000 47.49 ;
      RECT 300.000000 200.000000 400.000000 300.000000 45.94 ;
      RECT 200.000000 200.000000 300.000000 300.000000 44.44 ;
      RECT 100.000000 200.000000 200.000000 300.000000 49.52 ;
      RECT 0.000000 200.000000 100.000000 300.000000 50.20 ;
      RECT 500.000000 100.000000 565.632000 200.000000 40.16 ;
      RECT 400.000000 100.000000 500.000000 200.000000 44.72 ;
      RECT 300.000000 100.000000 400.000000 200.000000 40.02 ;
      RECT 200.000000 100.000000 300.000000 200.000000 42.45 ;
      RECT 100.000000 100.000000 200.000000 200.000000 40.02 ;
      RECT 0.000000 100.000000 100.000000 200.000000 44.70 ;
      RECT 500.000000 0.000000 565.632000 100.000000 49.94 ;
      RECT 400.000000 0.000000 500.000000 100.000000 49.74 ;
      RECT 300.000000 0.000000 400.000000 100.000000 45.26 ;
      RECT 200.000000 0.000000 300.000000 100.000000 53.90 ;
      RECT 100.000000 0.000000 200.000000 100.000000 45.50 ;
      RECT 0.000000 0.000000 100.000000 100.000000 53.90 ;
      LAYER M7 ;
      RECT 500.000000 300.000000 565.632000 358.128000 38.85 ;
      RECT 400.000000 300.000000 500.000000 358.128000 49.90 ;
      RECT 300.000000 300.000000 400.000000 358.128000 40.28 ;
      RECT 200.000000 300.000000 300.000000 358.128000 52.82 ;
      RECT 100.000000 300.000000 200.000000 358.128000 40.25 ;
      RECT 0.000000 300.000000 100.000000 358.128000 48.58 ;
      RECT 500.000000 200.000000 565.632000 300.000000 52.28 ;
      RECT 400.000000 200.000000 500.000000 300.000000 47.01 ;
      RECT 300.000000 200.000000 400.000000 300.000000 47.86 ;
      RECT 200.000000 200.000000 300.000000 300.000000 50.36 ;
      RECT 100.000000 200.000000 200.000000 300.000000 48.27 ;
      RECT 0.000000 200.000000 100.000000 300.000000 50.34 ;
      RECT 500.000000 100.000000 565.632000 200.000000 40.55 ;
      RECT 400.000000 100.000000 500.000000 200.000000 44.92 ;
      RECT 300.000000 100.000000 400.000000 200.000000 40.10 ;
      RECT 200.000000 100.000000 300.000000 200.000000 47.81 ;
      RECT 100.000000 100.000000 200.000000 200.000000 40.00 ;
      RECT 0.000000 100.000000 100.000000 200.000000 43.99 ;
      RECT 500.000000 0.000000 565.632000 100.000000 51.39 ;
      RECT 400.000000 0.000000 500.000000 100.000000 49.86 ;
      RECT 300.000000 0.000000 400.000000 100.000000 46.40 ;
      RECT 200.000000 0.000000 300.000000 100.000000 53.90 ;
      RECT 100.000000 0.000000 200.000000 100.000000 45.41 ;
      RECT 0.000000 0.000000 100.000000 100.000000 53.90 ;
      LAYER M8 ;
      RECT 500.000000 300.000000 565.632000 358.128000 43.38 ;
      RECT 400.000000 300.000000 500.000000 358.128000 43.77 ;
      RECT 300.000000 300.000000 400.000000 358.128000 43.77 ;
      RECT 200.000000 300.000000 300.000000 358.128000 43.77 ;
      RECT 100.000000 300.000000 200.000000 358.128000 43.77 ;
      RECT 0.000000 300.000000 100.000000 358.128000 43.53 ;
      RECT 500.000000 200.000000 565.632000 300.000000 44.24 ;
      RECT 400.000000 200.000000 500.000000 300.000000 44.64 ;
      RECT 300.000000 200.000000 400.000000 300.000000 44.64 ;
      RECT 200.000000 200.000000 300.000000 300.000000 44.64 ;
      RECT 100.000000 200.000000 200.000000 300.000000 44.64 ;
      RECT 0.000000 200.000000 100.000000 300.000000 44.40 ;
      RECT 500.000000 100.000000 565.632000 200.000000 43.88 ;
      RECT 400.000000 100.000000 500.000000 200.000000 44.28 ;
      RECT 300.000000 100.000000 400.000000 200.000000 44.28 ;
      RECT 200.000000 100.000000 300.000000 200.000000 44.28 ;
      RECT 100.000000 100.000000 200.000000 200.000000 44.28 ;
      RECT 0.000000 100.000000 100.000000 200.000000 44.04 ;
      RECT 500.000000 0.000000 565.632000 100.000000 43.65 ;
      RECT 400.000000 0.000000 500.000000 100.000000 44.04 ;
      RECT 300.000000 0.000000 400.000000 100.000000 44.04 ;
      RECT 200.000000 0.000000 300.000000 100.000000 44.04 ;
      RECT 100.000000 0.000000 200.000000 100.000000 44.04 ;
      RECT 0.000000 0.000000 100.000000 100.000000 43.80 ;
      LAYER M9 ;
      RECT 500.000000 300.000000 565.632000 358.128000 43.51 ;
      RECT 400.000000 300.000000 500.000000 358.128000 44.14 ;
      RECT 300.000000 300.000000 400.000000 358.128000 43.91 ;
      RECT 200.000000 300.000000 300.000000 358.128000 44.25 ;
      RECT 100.000000 300.000000 200.000000 358.128000 43.90 ;
      RECT 0.000000 300.000000 100.000000 358.128000 43.67 ;
      RECT 500.000000 200.000000 565.632000 300.000000 43.88 ;
      RECT 400.000000 200.000000 500.000000 300.000000 44.52 ;
      RECT 300.000000 200.000000 400.000000 300.000000 44.28 ;
      RECT 200.000000 200.000000 300.000000 300.000000 44.64 ;
      RECT 100.000000 200.000000 200.000000 300.000000 44.28 ;
      RECT 0.000000 200.000000 100.000000 300.000000 44.04 ;
      RECT 500.000000 100.000000 565.632000 200.000000 43.88 ;
      RECT 400.000000 100.000000 500.000000 200.000000 44.52 ;
      RECT 300.000000 100.000000 400.000000 200.000000 44.28 ;
      RECT 200.000000 100.000000 300.000000 200.000000 44.64 ;
      RECT 100.000000 100.000000 200.000000 200.000000 44.28 ;
      RECT 0.000000 100.000000 100.000000 200.000000 44.04 ;
      RECT 500.000000 0.000000 565.632000 100.000000 43.65 ;
      RECT 400.000000 0.000000 500.000000 100.000000 44.28 ;
      RECT 300.000000 0.000000 400.000000 100.000000 44.05 ;
      RECT 200.000000 0.000000 300.000000 100.000000 44.41 ;
      RECT 100.000000 0.000000 200.000000 100.000000 44.05 ;
      RECT 0.000000 0.000000 100.000000 100.000000 43.81 ;
      LAYER Pad ;
      RECT 500.000000 300.000000 565.632000 358.128000 22.12 ;
      RECT 400.000000 300.000000 500.000000 358.128000 22.65 ;
      RECT 300.000000 300.000000 400.000000 358.128000 22.39 ;
      RECT 200.000000 300.000000 300.000000 358.128000 19.82 ;
      RECT 100.000000 300.000000 200.000000 358.128000 22.26 ;
      RECT 0.000000 300.000000 100.000000 358.128000 19.35 ;
      RECT 500.000000 200.000000 565.632000 300.000000 22.20 ;
      RECT 400.000000 200.000000 500.000000 300.000000 22.42 ;
      RECT 300.000000 200.000000 400.000000 300.000000 23.03 ;
      RECT 200.000000 200.000000 300.000000 300.000000 23.23 ;
      RECT 100.000000 200.000000 200.000000 300.000000 23.10 ;
      RECT 0.000000 200.000000 100.000000 300.000000 22.71 ;
      RECT 500.000000 100.000000 565.632000 200.000000 22.46 ;
      RECT 400.000000 100.000000 500.000000 200.000000 23.07 ;
      RECT 300.000000 100.000000 400.000000 200.000000 23.43 ;
      RECT 200.000000 100.000000 300.000000 200.000000 23.41 ;
      RECT 100.000000 100.000000 200.000000 200.000000 23.15 ;
      RECT 0.000000 100.000000 100.000000 200.000000 22.89 ;
      RECT 500.000000 0.000000 565.632000 100.000000 21.93 ;
      RECT 400.000000 0.000000 500.000000 100.000000 22.16 ;
      RECT 300.000000 0.000000 400.000000 100.000000 22.90 ;
      RECT 200.000000 0.000000 300.000000 100.000000 22.84 ;
      RECT 100.000000 0.000000 200.000000 100.000000 22.37 ;
      RECT 0.000000 0.000000 100.000000 100.000000 22.32 ;
  END
END top_soc

END LIBRARY
